VERSION 5.8 ;
BUSBITCHARS "[]" ;
DIVIDERCHAR "/" ;
UNITS
    DATABASE MICRONS 1000 ;
END UNITS

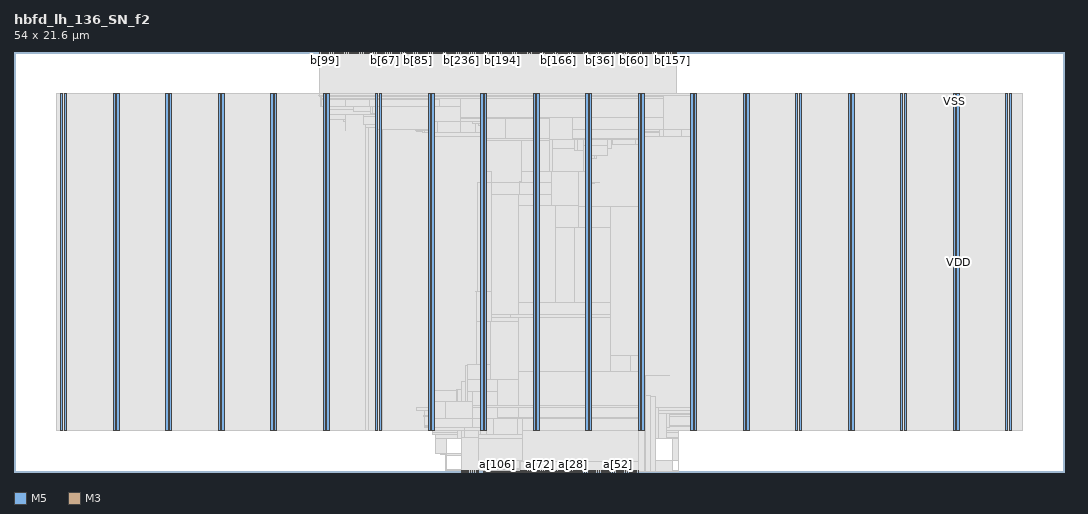
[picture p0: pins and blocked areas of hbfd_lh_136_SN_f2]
MACRO hbfd_lh_136_SN_f2
  FOREIGN hbfd_lh_136_SN_f2 0 0 ;
  CLASS BLOCK ;
  SIZE 54 BY 21.6 ;
  PIN a[0]
    DIRECTION INPUT ;
    USE SIGNAL ;
    PORT
      LAYER M5 ;
        RECT  26.064 0 26.088 0.084 ;
    END
  END a[0]
  PIN a[100]
    DIRECTION INPUT ;
    USE SIGNAL ;
    PORT
      LAYER M3 ;
        RECT  24.444 0 24.462 0.037 ;
    END
  END a[100]
  PIN a[101]
    DIRECTION INPUT ;
    USE SIGNAL ;
    PORT
      LAYER M3 ;
        RECT  24.516 0 24.534 0.037 ;
    END
  END a[101]
  PIN a[102]
    DIRECTION INPUT ;
    USE SIGNAL ;
    PORT
      LAYER M3 ;
        RECT  24.588 0 24.606 0.037 ;
    END
  END a[102]
  PIN a[103]
    DIRECTION INPUT ;
    USE SIGNAL ;
    PORT
      LAYER M3 ;
        RECT  24.66 0 24.678 0.037 ;
    END
  END a[103]
  PIN a[104]
    DIRECTION INPUT ;
    USE SIGNAL ;
    PORT
      LAYER M3 ;
        RECT  24.732 0 24.75 0.037 ;
    END
  END a[104]
  PIN a[105]
    DIRECTION INPUT ;
    USE SIGNAL ;
    PORT
      LAYER M3 ;
        RECT  24.804 0 24.822 0.037 ;
    END
  END a[105]
  PIN a[106]
    DIRECTION INPUT ;
    USE SIGNAL ;
    PORT
      LAYER M3 ;
        RECT  24.876 0 24.894 0.037 ;
    END
  END a[106]
  PIN a[107]
    DIRECTION INPUT ;
    USE SIGNAL ;
    PORT
      LAYER M3 ;
        RECT  24.948 0 24.966 0.037 ;
    END
  END a[107]
  PIN a[108]
    DIRECTION INPUT ;
    USE SIGNAL ;
    PORT
      LAYER M3 ;
        RECT  25.02 0 25.038 0.037 ;
    END
  END a[108]
  PIN a[109]
    DIRECTION INPUT ;
    USE SIGNAL ;
    PORT
      LAYER M3 ;
        RECT  25.092 0 25.11 0.037 ;
    END
  END a[109]
  PIN a[10]
    DIRECTION INPUT ;
    USE SIGNAL ;
    PORT
      LAYER M5 ;
        RECT  27.024 0 27.048 0.084 ;
    END
  END a[10]
  PIN a[110]
    DIRECTION INPUT ;
    USE SIGNAL ;
    PORT
      LAYER M3 ;
        RECT  25.164 0 25.182 0.037 ;
    END
  END a[110]
  PIN a[111]
    DIRECTION INPUT ;
    USE SIGNAL ;
    PORT
      LAYER M3 ;
        RECT  25.236 0 25.254 0.037 ;
    END
  END a[111]
  PIN a[112]
    DIRECTION INPUT ;
    USE SIGNAL ;
    PORT
      LAYER M3 ;
        RECT  25.308 0 25.326 0.037 ;
    END
  END a[112]
  PIN a[113]
    DIRECTION INPUT ;
    USE SIGNAL ;
    PORT
      LAYER M3 ;
        RECT  25.38 0 25.398 0.037 ;
    END
  END a[113]
  PIN a[114]
    DIRECTION INPUT ;
    USE SIGNAL ;
    PORT
      LAYER M3 ;
        RECT  25.452 0 25.47 0.037 ;
    END
  END a[114]
  PIN a[115]
    DIRECTION INPUT ;
    USE SIGNAL ;
    PORT
      LAYER M3 ;
        RECT  25.524 0 25.542 0.037 ;
    END
  END a[115]
  PIN a[116]
    DIRECTION INPUT ;
    USE SIGNAL ;
    PORT
      LAYER M3 ;
        RECT  25.596 0 25.614 0.037 ;
    END
  END a[116]
  PIN a[117]
    DIRECTION INPUT ;
    USE SIGNAL ;
    PORT
      LAYER M3 ;
        RECT  25.668 0 25.686 0.037 ;
    END
  END a[117]
  PIN a[118]
    DIRECTION INPUT ;
    USE SIGNAL ;
    PORT
      LAYER M3 ;
        RECT  25.74 0 25.758 0.037 ;
    END
  END a[118]
  PIN a[119]
    DIRECTION INPUT ;
    USE SIGNAL ;
    PORT
      LAYER M3 ;
        RECT  25.812 0 25.83 0.037 ;
    END
  END a[119]
  PIN a[11]
    DIRECTION INPUT ;
    USE SIGNAL ;
    PORT
      LAYER M5 ;
        RECT  27.12 0 27.144 0.084 ;
    END
  END a[11]
  PIN a[120]
    DIRECTION INPUT ;
    USE SIGNAL ;
    PORT
      LAYER M3 ;
        RECT  25.884 0 25.902 0.037 ;
    END
  END a[120]
  PIN a[121]
    DIRECTION INPUT ;
    USE SIGNAL ;
    PORT
      LAYER M3 ;
        RECT  25.956 0 25.974 0.037 ;
    END
  END a[121]
  PIN a[122]
    DIRECTION INPUT ;
    USE SIGNAL ;
    PORT
      LAYER M3 ;
        RECT  26.028 0 26.046 0.037 ;
    END
  END a[122]
  PIN a[123]
    DIRECTION INPUT ;
    USE SIGNAL ;
    PORT
      LAYER M3 ;
        RECT  26.1 0 26.118 0.037 ;
    END
  END a[123]
  PIN a[124]
    DIRECTION INPUT ;
    USE SIGNAL ;
    PORT
      LAYER M3 ;
        RECT  26.172 0 26.19 0.037 ;
    END
  END a[124]
  PIN a[125]
    DIRECTION INPUT ;
    USE SIGNAL ;
    PORT
      LAYER M3 ;
        RECT  26.244 0 26.262 0.037 ;
    END
  END a[125]
  PIN a[126]
    DIRECTION INPUT ;
    USE SIGNAL ;
    PORT
      LAYER M3 ;
        RECT  26.316 0 26.334 0.037 ;
    END
  END a[126]
  PIN a[127]
    DIRECTION INPUT ;
    USE SIGNAL ;
    PORT
      LAYER M3 ;
        RECT  26.388 0 26.406 0.037 ;
    END
  END a[127]
  PIN a[128]
    DIRECTION INPUT ;
    USE SIGNAL ;
    PORT
      LAYER M5 ;
        RECT  22.992 0 23.016 0.084 ;
    END
  END a[128]
  PIN a[129]
    DIRECTION INPUT ;
    USE SIGNAL ;
    PORT
      LAYER M5 ;
        RECT  23.088 0 23.112 0.084 ;
    END
  END a[129]
  PIN a[12]
    DIRECTION INPUT ;
    USE SIGNAL ;
    PORT
      LAYER M5 ;
        RECT  27.216 0 27.24 0.084 ;
    END
  END a[12]
  PIN a[130]
    DIRECTION INPUT ;
    USE SIGNAL ;
    PORT
      LAYER M5 ;
        RECT  23.184 0 23.208 0.084 ;
    END
  END a[130]
  PIN a[131]
    DIRECTION INPUT ;
    USE SIGNAL ;
    PORT
      LAYER M5 ;
        RECT  23.28 0 23.304 0.084 ;
    END
  END a[131]
  PIN a[132]
    DIRECTION INPUT ;
    USE SIGNAL ;
    PORT
      LAYER M5 ;
        RECT  23.376 0 23.4 0.084 ;
    END
  END a[132]
  PIN a[133]
    DIRECTION INPUT ;
    USE SIGNAL ;
    PORT
      LAYER M5 ;
        RECT  23.472 0 23.496 0.084 ;
    END
  END a[133]
  PIN a[134]
    DIRECTION INPUT ;
    USE SIGNAL ;
    PORT
      LAYER M5 ;
        RECT  23.568 0 23.592 0.084 ;
    END
  END a[134]
  PIN a[135]
    DIRECTION INPUT ;
    USE SIGNAL ;
    PORT
      LAYER M5 ;
        RECT  23.664 0 23.688 0.084 ;
    END
  END a[135]
  PIN a[13]
    DIRECTION INPUT ;
    USE SIGNAL ;
    PORT
      LAYER M5 ;
        RECT  27.312 0 27.336 0.084 ;
    END
  END a[13]
  PIN a[14]
    DIRECTION INPUT ;
    USE SIGNAL ;
    PORT
      LAYER M5 ;
        RECT  27.408 0 27.432 0.084 ;
    END
  END a[14]
  PIN a[15]
    DIRECTION INPUT ;
    USE SIGNAL ;
    PORT
      LAYER M5 ;
        RECT  27.504 0 27.528 0.084 ;
    END
  END a[15]
  PIN a[16]
    DIRECTION INPUT ;
    USE SIGNAL ;
    PORT
      LAYER M5 ;
        RECT  27.6 0 27.624 0.084 ;
    END
  END a[16]
  PIN a[17]
    DIRECTION INPUT ;
    USE SIGNAL ;
    PORT
      LAYER M5 ;
        RECT  27.696 0 27.72 0.084 ;
    END
  END a[17]
  PIN a[18]
    DIRECTION INPUT ;
    USE SIGNAL ;
    PORT
      LAYER M5 ;
        RECT  27.792 0 27.816 0.084 ;
    END
  END a[18]
  PIN a[19]
    DIRECTION INPUT ;
    USE SIGNAL ;
    PORT
      LAYER M5 ;
        RECT  27.888 0 27.912 0.084 ;
    END
  END a[19]
  PIN a[1]
    DIRECTION INPUT ;
    USE SIGNAL ;
    PORT
      LAYER M5 ;
        RECT  26.16 0 26.184 0.084 ;
    END
  END a[1]
  PIN a[20]
    DIRECTION INPUT ;
    USE SIGNAL ;
    PORT
      LAYER M5 ;
        RECT  27.984 0 28.008 0.084 ;
    END
  END a[20]
  PIN a[21]
    DIRECTION INPUT ;
    USE SIGNAL ;
    PORT
      LAYER M5 ;
        RECT  28.08 0 28.104 0.084 ;
    END
  END a[21]
  PIN a[22]
    DIRECTION INPUT ;
    USE SIGNAL ;
    PORT
      LAYER M5 ;
        RECT  28.176 0 28.2 0.084 ;
    END
  END a[22]
  PIN a[23]
    DIRECTION INPUT ;
    USE SIGNAL ;
    PORT
      LAYER M5 ;
        RECT  28.272 0 28.296 0.084 ;
    END
  END a[23]
  PIN a[24]
    DIRECTION INPUT ;
    USE SIGNAL ;
    PORT
      LAYER M5 ;
        RECT  28.368 0 28.392 0.084 ;
    END
  END a[24]
  PIN a[25]
    DIRECTION INPUT ;
    USE SIGNAL ;
    PORT
      LAYER M5 ;
        RECT  28.464 0 28.488 0.084 ;
    END
  END a[25]
  PIN a[26]
    DIRECTION INPUT ;
    USE SIGNAL ;
    PORT
      LAYER M5 ;
        RECT  28.56 0 28.584 0.084 ;
    END
  END a[26]
  PIN a[27]
    DIRECTION INPUT ;
    USE SIGNAL ;
    PORT
      LAYER M5 ;
        RECT  28.656 0 28.68 0.084 ;
    END
  END a[27]
  PIN a[28]
    DIRECTION INPUT ;
    USE SIGNAL ;
    PORT
      LAYER M5 ;
        RECT  28.752 0 28.776 0.084 ;
    END
  END a[28]
  PIN a[29]
    DIRECTION INPUT ;
    USE SIGNAL ;
    PORT
      LAYER M5 ;
        RECT  28.848 0 28.872 0.084 ;
    END
  END a[29]
  PIN a[2]
    DIRECTION INPUT ;
    USE SIGNAL ;
    PORT
      LAYER M5 ;
        RECT  26.256 0 26.28 0.084 ;
    END
  END a[2]
  PIN a[30]
    DIRECTION INPUT ;
    USE SIGNAL ;
    PORT
      LAYER M5 ;
        RECT  28.944 0 28.968 0.084 ;
    END
  END a[30]
  PIN a[31]
    DIRECTION INPUT ;
    USE SIGNAL ;
    PORT
      LAYER M5 ;
        RECT  29.04 0 29.064 0.084 ;
    END
  END a[31]
  PIN a[32]
    DIRECTION INPUT ;
    USE SIGNAL ;
    PORT
      LAYER M5 ;
        RECT  29.136 0 29.16 0.084 ;
    END
  END a[32]
  PIN a[33]
    DIRECTION INPUT ;
    USE SIGNAL ;
    PORT
      LAYER M5 ;
        RECT  29.232 0 29.256 0.084 ;
    END
  END a[33]
  PIN a[34]
    DIRECTION INPUT ;
    USE SIGNAL ;
    PORT
      LAYER M5 ;
        RECT  29.328 0 29.352 0.084 ;
    END
  END a[34]
  PIN a[35]
    DIRECTION INPUT ;
    USE SIGNAL ;
    PORT
      LAYER M5 ;
        RECT  29.424 0 29.448 0.084 ;
    END
  END a[35]
  PIN a[36]
    DIRECTION INPUT ;
    USE SIGNAL ;
    PORT
      LAYER M5 ;
        RECT  29.52 0 29.544 0.084 ;
    END
  END a[36]
  PIN a[37]
    DIRECTION INPUT ;
    USE SIGNAL ;
    PORT
      LAYER M5 ;
        RECT  29.616 0 29.64 0.084 ;
    END
  END a[37]
  PIN a[38]
    DIRECTION INPUT ;
    USE SIGNAL ;
    PORT
      LAYER M5 ;
        RECT  29.712 0 29.736 0.084 ;
    END
  END a[38]
  PIN a[39]
    DIRECTION INPUT ;
    USE SIGNAL ;
    PORT
      LAYER M5 ;
        RECT  29.808 0 29.832 0.084 ;
    END
  END a[39]
  PIN a[3]
    DIRECTION INPUT ;
    USE SIGNAL ;
    PORT
      LAYER M5 ;
        RECT  26.352 0 26.376 0.084 ;
    END
  END a[3]
  PIN a[40]
    DIRECTION INPUT ;
    USE SIGNAL ;
    PORT
      LAYER M5 ;
        RECT  29.904 0 29.928 0.084 ;
    END
  END a[40]
  PIN a[41]
    DIRECTION INPUT ;
    USE SIGNAL ;
    PORT
      LAYER M5 ;
        RECT  30 0 30.024 0.084 ;
    END
  END a[41]
  PIN a[42]
    DIRECTION INPUT ;
    USE SIGNAL ;
    PORT
      LAYER M5 ;
        RECT  30.096 0 30.12 0.084 ;
    END
  END a[42]
  PIN a[43]
    DIRECTION INPUT ;
    USE SIGNAL ;
    PORT
      LAYER M5 ;
        RECT  30.192 0 30.216 0.084 ;
    END
  END a[43]
  PIN a[44]
    DIRECTION INPUT ;
    USE SIGNAL ;
    PORT
      LAYER M5 ;
        RECT  30.288 0 30.312 0.084 ;
    END
  END a[44]
  PIN a[45]
    DIRECTION INPUT ;
    USE SIGNAL ;
    PORT
      LAYER M5 ;
        RECT  30.384 0 30.408 0.084 ;
    END
  END a[45]
  PIN a[46]
    DIRECTION INPUT ;
    USE SIGNAL ;
    PORT
      LAYER M5 ;
        RECT  30.48 0 30.504 0.084 ;
    END
  END a[46]
  PIN a[47]
    DIRECTION INPUT ;
    USE SIGNAL ;
    PORT
      LAYER M5 ;
        RECT  30.576 0 30.6 0.084 ;
    END
  END a[47]
  PIN a[48]
    DIRECTION INPUT ;
    USE SIGNAL ;
    PORT
      LAYER M5 ;
        RECT  30.672 0 30.696 0.084 ;
    END
  END a[48]
  PIN a[49]
    DIRECTION INPUT ;
    USE SIGNAL ;
    PORT
      LAYER M5 ;
        RECT  30.768 0 30.792 0.084 ;
    END
  END a[49]
  PIN a[4]
    DIRECTION INPUT ;
    USE SIGNAL ;
    PORT
      LAYER M5 ;
        RECT  26.448 0 26.472 0.084 ;
    END
  END a[4]
  PIN a[50]
    DIRECTION INPUT ;
    USE SIGNAL ;
    PORT
      LAYER M5 ;
        RECT  30.864 0 30.888 0.084 ;
    END
  END a[50]
  PIN a[51]
    DIRECTION INPUT ;
    USE SIGNAL ;
    PORT
      LAYER M5 ;
        RECT  30.96 0 30.984 0.084 ;
    END
  END a[51]
  PIN a[52]
    DIRECTION INPUT ;
    USE SIGNAL ;
    PORT
      LAYER M5 ;
        RECT  31.056 0 31.08 0.084 ;
    END
  END a[52]
  PIN a[53]
    DIRECTION INPUT ;
    USE SIGNAL ;
    PORT
      LAYER M5 ;
        RECT  31.152 0 31.176 0.084 ;
    END
  END a[53]
  PIN a[54]
    DIRECTION INPUT ;
    USE SIGNAL ;
    PORT
      LAYER M5 ;
        RECT  31.248 0 31.272 0.084 ;
    END
  END a[54]
  PIN a[55]
    DIRECTION INPUT ;
    USE SIGNAL ;
    PORT
      LAYER M5 ;
        RECT  31.344 0 31.368 0.084 ;
    END
  END a[55]
  PIN a[56]
    DIRECTION INPUT ;
    USE SIGNAL ;
    PORT
      LAYER M5 ;
        RECT  31.44 0 31.464 0.084 ;
    END
  END a[56]
  PIN a[57]
    DIRECTION INPUT ;
    USE SIGNAL ;
    PORT
      LAYER M5 ;
        RECT  31.536 0 31.56 0.084 ;
    END
  END a[57]
  PIN a[58]
    DIRECTION INPUT ;
    USE SIGNAL ;
    PORT
      LAYER M5 ;
        RECT  31.632 0 31.656 0.084 ;
    END
  END a[58]
  PIN a[59]
    DIRECTION INPUT ;
    USE SIGNAL ;
    PORT
      LAYER M5 ;
        RECT  31.728 0 31.752 0.084 ;
    END
  END a[59]
  PIN a[5]
    DIRECTION INPUT ;
    USE SIGNAL ;
    PORT
      LAYER M5 ;
        RECT  26.544 0 26.568 0.084 ;
    END
  END a[5]
  PIN a[60]
    DIRECTION INPUT ;
    USE SIGNAL ;
    PORT
      LAYER M5 ;
        RECT  31.824 0 31.848 0.084 ;
    END
  END a[60]
  PIN a[61]
    DIRECTION INPUT ;
    USE SIGNAL ;
    PORT
      LAYER M5 ;
        RECT  31.92 0 31.944 0.084 ;
    END
  END a[61]
  PIN a[62]
    DIRECTION INPUT ;
    USE SIGNAL ;
    PORT
      LAYER M5 ;
        RECT  32.016 0 32.04 0.084 ;
    END
  END a[62]
  PIN a[63]
    DIRECTION INPUT ;
    USE SIGNAL ;
    PORT
      LAYER M5 ;
        RECT  32.112 0 32.136 0.084 ;
    END
  END a[63]
  PIN a[64]
    DIRECTION INPUT ;
    USE SIGNAL ;
    PORT
      LAYER M3 ;
        RECT  26.46 0 26.478 0.037 ;
    END
  END a[64]
  PIN a[65]
    DIRECTION INPUT ;
    USE SIGNAL ;
    PORT
      LAYER M3 ;
        RECT  26.532 0 26.55 0.037 ;
    END
  END a[65]
  PIN a[66]
    DIRECTION INPUT ;
    USE SIGNAL ;
    PORT
      LAYER M3 ;
        RECT  26.604 0 26.622 0.037 ;
    END
  END a[66]
  PIN a[67]
    DIRECTION INPUT ;
    USE SIGNAL ;
    PORT
      LAYER M3 ;
        RECT  26.676 0 26.694 0.037 ;
    END
  END a[67]
  PIN a[68]
    DIRECTION INPUT ;
    USE SIGNAL ;
    PORT
      LAYER M3 ;
        RECT  26.748 0 26.766 0.037 ;
    END
  END a[68]
  PIN a[69]
    DIRECTION INPUT ;
    USE SIGNAL ;
    PORT
      LAYER M3 ;
        RECT  26.82 0 26.838 0.037 ;
    END
  END a[69]
  PIN a[6]
    DIRECTION INPUT ;
    USE SIGNAL ;
    PORT
      LAYER M5 ;
        RECT  26.64 0 26.664 0.084 ;
    END
  END a[6]
  PIN a[70]
    DIRECTION INPUT ;
    USE SIGNAL ;
    PORT
      LAYER M3 ;
        RECT  26.892 0 26.91 0.037 ;
    END
  END a[70]
  PIN a[71]
    DIRECTION INPUT ;
    USE SIGNAL ;
    PORT
      LAYER M3 ;
        RECT  26.964 0 26.982 0.037 ;
    END
  END a[71]
  PIN a[72]
    DIRECTION INPUT ;
    USE SIGNAL ;
    PORT
      LAYER M3 ;
        RECT  27.036 0 27.054 0.037 ;
    END
  END a[72]
  PIN a[73]
    DIRECTION INPUT ;
    USE SIGNAL ;
    PORT
      LAYER M3 ;
        RECT  27.108 0 27.126 0.037 ;
    END
  END a[73]
  PIN a[74]
    DIRECTION INPUT ;
    USE SIGNAL ;
    PORT
      LAYER M3 ;
        RECT  27.18 0 27.198 0.037 ;
    END
  END a[74]
  PIN a[75]
    DIRECTION INPUT ;
    USE SIGNAL ;
    PORT
      LAYER M3 ;
        RECT  27.252 0 27.27 0.037 ;
    END
  END a[75]
  PIN a[76]
    DIRECTION INPUT ;
    USE SIGNAL ;
    PORT
      LAYER M3 ;
        RECT  27.324 0 27.342 0.037 ;
    END
  END a[76]
  PIN a[77]
    DIRECTION INPUT ;
    USE SIGNAL ;
    PORT
      LAYER M3 ;
        RECT  27.396 0 27.414 0.037 ;
    END
  END a[77]
  PIN a[78]
    DIRECTION INPUT ;
    USE SIGNAL ;
    PORT
      LAYER M3 ;
        RECT  27.468 0 27.486 0.037 ;
    END
  END a[78]
  PIN a[79]
    DIRECTION INPUT ;
    USE SIGNAL ;
    PORT
      LAYER M3 ;
        RECT  27.54 0 27.558 0.037 ;
    END
  END a[79]
  PIN a[7]
    DIRECTION INPUT ;
    USE SIGNAL ;
    PORT
      LAYER M5 ;
        RECT  26.736 0 26.76 0.084 ;
    END
  END a[7]
  PIN a[80]
    DIRECTION INPUT ;
    USE SIGNAL ;
    PORT
      LAYER M3 ;
        RECT  27.612 0 27.63 0.037 ;
    END
  END a[80]
  PIN a[81]
    DIRECTION INPUT ;
    USE SIGNAL ;
    PORT
      LAYER M3 ;
        RECT  27.684 0 27.702 0.037 ;
    END
  END a[81]
  PIN a[82]
    DIRECTION INPUT ;
    USE SIGNAL ;
    PORT
      LAYER M3 ;
        RECT  27.756 0 27.774 0.037 ;
    END
  END a[82]
  PIN a[83]
    DIRECTION INPUT ;
    USE SIGNAL ;
    PORT
      LAYER M3 ;
        RECT  27.828 0 27.846 0.037 ;
    END
  END a[83]
  PIN a[84]
    DIRECTION INPUT ;
    USE SIGNAL ;
    PORT
      LAYER M3 ;
        RECT  27.9 0 27.918 0.037 ;
    END
  END a[84]
  PIN a[85]
    DIRECTION INPUT ;
    USE SIGNAL ;
    PORT
      LAYER M3 ;
        RECT  27.972 0 27.99 0.037 ;
    END
  END a[85]
  PIN a[86]
    DIRECTION INPUT ;
    USE SIGNAL ;
    PORT
      LAYER M3 ;
        RECT  28.044 0 28.062 0.037 ;
    END
  END a[86]
  PIN a[87]
    DIRECTION INPUT ;
    USE SIGNAL ;
    PORT
      LAYER M3 ;
        RECT  28.116 0 28.134 0.037 ;
    END
  END a[87]
  PIN a[88]
    DIRECTION INPUT ;
    USE SIGNAL ;
    PORT
      LAYER M3 ;
        RECT  28.188 0 28.206 0.037 ;
    END
  END a[88]
  PIN a[89]
    DIRECTION INPUT ;
    USE SIGNAL ;
    PORT
      LAYER M3 ;
        RECT  28.26 0 28.278 0.037 ;
    END
  END a[89]
  PIN a[8]
    DIRECTION INPUT ;
    USE SIGNAL ;
    PORT
      LAYER M5 ;
        RECT  26.832 0 26.856 0.084 ;
    END
  END a[8]
  PIN a[90]
    DIRECTION INPUT ;
    USE SIGNAL ;
    PORT
      LAYER M3 ;
        RECT  28.332 0 28.35 0.037 ;
    END
  END a[90]
  PIN a[91]
    DIRECTION INPUT ;
    USE SIGNAL ;
    PORT
      LAYER M3 ;
        RECT  28.404 0 28.422 0.037 ;
    END
  END a[91]
  PIN a[92]
    DIRECTION INPUT ;
    USE SIGNAL ;
    PORT
      LAYER M3 ;
        RECT  28.476 0 28.494 0.037 ;
    END
  END a[92]
  PIN a[93]
    DIRECTION INPUT ;
    USE SIGNAL ;
    PORT
      LAYER M3 ;
        RECT  28.548 0 28.566 0.037 ;
    END
  END a[93]
  PIN a[94]
    DIRECTION INPUT ;
    USE SIGNAL ;
    PORT
      LAYER M3 ;
        RECT  28.62 0 28.638 0.037 ;
    END
  END a[94]
  PIN a[95]
    DIRECTION INPUT ;
    USE SIGNAL ;
    PORT
      LAYER M3 ;
        RECT  28.692 0 28.71 0.037 ;
    END
  END a[95]
  PIN a[96]
    DIRECTION INPUT ;
    USE SIGNAL ;
    PORT
      LAYER M3 ;
        RECT  24.156 0 24.174 0.037 ;
    END
  END a[96]
  PIN a[97]
    DIRECTION INPUT ;
    USE SIGNAL ;
    PORT
      LAYER M3 ;
        RECT  24.228 0 24.246 0.037 ;
    END
  END a[97]
  PIN a[98]
    DIRECTION INPUT ;
    USE SIGNAL ;
    PORT
      LAYER M3 ;
        RECT  24.3 0 24.318 0.037 ;
    END
  END a[98]
  PIN a[99]
    DIRECTION INPUT ;
    USE SIGNAL ;
    PORT
      LAYER M3 ;
        RECT  24.372 0 24.39 0.037 ;
    END
  END a[99]
  PIN a[9]
    DIRECTION INPUT ;
    USE SIGNAL ;
    PORT
      LAYER M5 ;
        RECT  26.928 0 26.952 0.084 ;
    END
  END a[9]
  PIN b[0]
    DIRECTION OUTPUT ;
    USE SIGNAL ;
    PORT
      LAYER M5 ;
        RECT  27.984 21.516 28.008 21.6 ;
    END
  END b[0]
  PIN b[100]
    DIRECTION OUTPUT ;
    USE SIGNAL ;
    PORT
      LAYER M5 ;
        RECT  16.08 21.516 16.104 21.6 ;
    END
  END b[100]
  PIN b[101]
    DIRECTION OUTPUT ;
    USE SIGNAL ;
    PORT
      LAYER M5 ;
        RECT  16.176 21.516 16.2 21.6 ;
    END
  END b[101]
  PIN b[102]
    DIRECTION OUTPUT ;
    USE SIGNAL ;
    PORT
      LAYER M5 ;
        RECT  16.272 21.516 16.296 21.6 ;
    END
  END b[102]
  PIN b[103]
    DIRECTION OUTPUT ;
    USE SIGNAL ;
    PORT
      LAYER M5 ;
        RECT  16.368 21.516 16.392 21.6 ;
    END
  END b[103]
  PIN b[104]
    DIRECTION OUTPUT ;
    USE SIGNAL ;
    PORT
      LAYER M5 ;
        RECT  16.464 21.516 16.488 21.6 ;
    END
  END b[104]
  PIN b[105]
    DIRECTION OUTPUT ;
    USE SIGNAL ;
    PORT
      LAYER M5 ;
        RECT  16.56 21.516 16.584 21.6 ;
    END
  END b[105]
  PIN b[106]
    DIRECTION OUTPUT ;
    USE SIGNAL ;
    PORT
      LAYER M5 ;
        RECT  16.656 21.516 16.68 21.6 ;
    END
  END b[106]
  PIN b[107]
    DIRECTION OUTPUT ;
    USE SIGNAL ;
    PORT
      LAYER M5 ;
        RECT  16.752 21.516 16.776 21.6 ;
    END
  END b[107]
  PIN b[108]
    DIRECTION OUTPUT ;
    USE SIGNAL ;
    PORT
      LAYER M5 ;
        RECT  16.848 21.516 16.872 21.6 ;
    END
  END b[108]
  PIN b[109]
    DIRECTION OUTPUT ;
    USE SIGNAL ;
    PORT
      LAYER M5 ;
        RECT  16.944 21.516 16.968 21.6 ;
    END
  END b[109]
  PIN b[10]
    DIRECTION OUTPUT ;
    USE SIGNAL ;
    PORT
      LAYER M5 ;
        RECT  28.944 21.516 28.968 21.6 ;
    END
  END b[10]
  PIN b[110]
    DIRECTION OUTPUT ;
    USE SIGNAL ;
    PORT
      LAYER M5 ;
        RECT  17.04 21.516 17.064 21.6 ;
    END
  END b[110]
  PIN b[111]
    DIRECTION OUTPUT ;
    USE SIGNAL ;
    PORT
      LAYER M5 ;
        RECT  17.136 21.516 17.16 21.6 ;
    END
  END b[111]
  PIN b[112]
    DIRECTION OUTPUT ;
    USE SIGNAL ;
    PORT
      LAYER M5 ;
        RECT  17.232 21.516 17.256 21.6 ;
    END
  END b[112]
  PIN b[113]
    DIRECTION OUTPUT ;
    USE SIGNAL ;
    PORT
      LAYER M5 ;
        RECT  17.328 21.516 17.352 21.6 ;
    END
  END b[113]
  PIN b[114]
    DIRECTION OUTPUT ;
    USE SIGNAL ;
    PORT
      LAYER M5 ;
        RECT  17.424 21.516 17.448 21.6 ;
    END
  END b[114]
  PIN b[115]
    DIRECTION OUTPUT ;
    USE SIGNAL ;
    PORT
      LAYER M5 ;
        RECT  17.52 21.516 17.544 21.6 ;
    END
  END b[115]
  PIN b[116]
    DIRECTION OUTPUT ;
    USE SIGNAL ;
    PORT
      LAYER M5 ;
        RECT  17.616 21.516 17.64 21.6 ;
    END
  END b[116]
  PIN b[117]
    DIRECTION OUTPUT ;
    USE SIGNAL ;
    PORT
      LAYER M5 ;
        RECT  17.712 21.516 17.736 21.6 ;
    END
  END b[117]
  PIN b[118]
    DIRECTION OUTPUT ;
    USE SIGNAL ;
    PORT
      LAYER M5 ;
        RECT  17.808 21.516 17.832 21.6 ;
    END
  END b[118]
  PIN b[119]
    DIRECTION OUTPUT ;
    USE SIGNAL ;
    PORT
      LAYER M5 ;
        RECT  17.904 21.516 17.928 21.6 ;
    END
  END b[119]
  PIN b[11]
    DIRECTION OUTPUT ;
    USE SIGNAL ;
    PORT
      LAYER M5 ;
        RECT  29.04 21.516 29.064 21.6 ;
    END
  END b[11]
  PIN b[120]
    DIRECTION OUTPUT ;
    USE SIGNAL ;
    PORT
      LAYER M5 ;
        RECT  18 21.516 18.024 21.6 ;
    END
  END b[120]
  PIN b[121]
    DIRECTION OUTPUT ;
    USE SIGNAL ;
    PORT
      LAYER M5 ;
        RECT  18.096 21.516 18.12 21.6 ;
    END
  END b[121]
  PIN b[122]
    DIRECTION OUTPUT ;
    USE SIGNAL ;
    PORT
      LAYER M5 ;
        RECT  18.192 21.516 18.216 21.6 ;
    END
  END b[122]
  PIN b[123]
    DIRECTION OUTPUT ;
    USE SIGNAL ;
    PORT
      LAYER M5 ;
        RECT  18.288 21.516 18.312 21.6 ;
    END
  END b[123]
  PIN b[124]
    DIRECTION OUTPUT ;
    USE SIGNAL ;
    PORT
      LAYER M5 ;
        RECT  18.384 21.516 18.408 21.6 ;
    END
  END b[124]
  PIN b[125]
    DIRECTION OUTPUT ;
    USE SIGNAL ;
    PORT
      LAYER M5 ;
        RECT  18.48 21.516 18.504 21.6 ;
    END
  END b[125]
  PIN b[126]
    DIRECTION OUTPUT ;
    USE SIGNAL ;
    PORT
      LAYER M5 ;
        RECT  18.576 21.516 18.6 21.6 ;
    END
  END b[126]
  PIN b[127]
    DIRECTION OUTPUT ;
    USE SIGNAL ;
    PORT
      LAYER M5 ;
        RECT  18.672 21.516 18.696 21.6 ;
    END
  END b[127]
  PIN b[128]
    DIRECTION OUTPUT ;
    USE SIGNAL ;
    PORT
      LAYER M5 ;
        RECT  31.056 21.516 31.08 21.6 ;
    END
  END b[128]
  PIN b[129]
    DIRECTION OUTPUT ;
    USE SIGNAL ;
    PORT
      LAYER M5 ;
        RECT  31.152 21.516 31.176 21.6 ;
    END
  END b[129]
  PIN b[12]
    DIRECTION OUTPUT ;
    USE SIGNAL ;
    PORT
      LAYER M5 ;
        RECT  29.136 21.516 29.16 21.6 ;
    END
  END b[12]
  PIN b[130]
    DIRECTION OUTPUT ;
    USE SIGNAL ;
    PORT
      LAYER M5 ;
        RECT  31.248 21.516 31.272 21.6 ;
    END
  END b[130]
  PIN b[131]
    DIRECTION OUTPUT ;
    USE SIGNAL ;
    PORT
      LAYER M5 ;
        RECT  31.344 21.516 31.368 21.6 ;
    END
  END b[131]
  PIN b[132]
    DIRECTION OUTPUT ;
    USE SIGNAL ;
    PORT
      LAYER M5 ;
        RECT  31.44 21.516 31.464 21.6 ;
    END
  END b[132]
  PIN b[133]
    DIRECTION OUTPUT ;
    USE SIGNAL ;
    PORT
      LAYER M5 ;
        RECT  31.536 21.516 31.56 21.6 ;
    END
  END b[133]
  PIN b[134]
    DIRECTION OUTPUT ;
    USE SIGNAL ;
    PORT
      LAYER M5 ;
        RECT  31.632 21.516 31.656 21.6 ;
    END
  END b[134]
  PIN b[135]
    DIRECTION OUTPUT ;
    USE SIGNAL ;
    PORT
      LAYER M5 ;
        RECT  31.728 21.516 31.752 21.6 ;
    END
  END b[135]
  PIN b[136]
    DIRECTION OUTPUT ;
    USE SIGNAL ;
    PORT
      LAYER M5 ;
        RECT  31.824 21.516 31.848 21.6 ;
    END
  END b[136]
  PIN b[137]
    DIRECTION OUTPUT ;
    USE SIGNAL ;
    PORT
      LAYER M5 ;
        RECT  31.92 21.516 31.944 21.6 ;
    END
  END b[137]
  PIN b[138]
    DIRECTION OUTPUT ;
    USE SIGNAL ;
    PORT
      LAYER M5 ;
        RECT  32.016 21.516 32.04 21.6 ;
    END
  END b[138]
  PIN b[139]
    DIRECTION OUTPUT ;
    USE SIGNAL ;
    PORT
      LAYER M5 ;
        RECT  32.112 21.516 32.136 21.6 ;
    END
  END b[139]
  PIN b[13]
    DIRECTION OUTPUT ;
    USE SIGNAL ;
    PORT
      LAYER M5 ;
        RECT  29.232 21.516 29.256 21.6 ;
    END
  END b[13]
  PIN b[140]
    DIRECTION OUTPUT ;
    USE SIGNAL ;
    PORT
      LAYER M5 ;
        RECT  32.208 21.516 32.232 21.6 ;
    END
  END b[140]
  PIN b[141]
    DIRECTION OUTPUT ;
    USE SIGNAL ;
    PORT
      LAYER M5 ;
        RECT  32.304 21.516 32.328 21.6 ;
    END
  END b[141]
  PIN b[142]
    DIRECTION OUTPUT ;
    USE SIGNAL ;
    PORT
      LAYER M5 ;
        RECT  32.4 21.516 32.424 21.6 ;
    END
  END b[142]
  PIN b[143]
    DIRECTION OUTPUT ;
    USE SIGNAL ;
    PORT
      LAYER M5 ;
        RECT  32.496 21.516 32.52 21.6 ;
    END
  END b[143]
  PIN b[144]
    DIRECTION OUTPUT ;
    USE SIGNAL ;
    PORT
      LAYER M5 ;
        RECT  32.592 21.516 32.616 21.6 ;
    END
  END b[144]
  PIN b[145]
    DIRECTION OUTPUT ;
    USE SIGNAL ;
    PORT
      LAYER M5 ;
        RECT  32.688 21.516 32.712 21.6 ;
    END
  END b[145]
  PIN b[146]
    DIRECTION OUTPUT ;
    USE SIGNAL ;
    PORT
      LAYER M5 ;
        RECT  32.784 21.516 32.808 21.6 ;
    END
  END b[146]
  PIN b[147]
    DIRECTION OUTPUT ;
    USE SIGNAL ;
    PORT
      LAYER M5 ;
        RECT  32.88 21.516 32.904 21.6 ;
    END
  END b[147]
  PIN b[148]
    DIRECTION OUTPUT ;
    USE SIGNAL ;
    PORT
      LAYER M5 ;
        RECT  32.976 21.516 33 21.6 ;
    END
  END b[148]
  PIN b[149]
    DIRECTION OUTPUT ;
    USE SIGNAL ;
    PORT
      LAYER M5 ;
        RECT  33.072 21.516 33.096 21.6 ;
    END
  END b[149]
  PIN b[14]
    DIRECTION OUTPUT ;
    USE SIGNAL ;
    PORT
      LAYER M5 ;
        RECT  29.328 21.516 29.352 21.6 ;
    END
  END b[14]
  PIN b[150]
    DIRECTION OUTPUT ;
    USE SIGNAL ;
    PORT
      LAYER M5 ;
        RECT  33.168 21.516 33.192 21.6 ;
    END
  END b[150]
  PIN b[151]
    DIRECTION OUTPUT ;
    USE SIGNAL ;
    PORT
      LAYER M5 ;
        RECT  33.264 21.516 33.288 21.6 ;
    END
  END b[151]
  PIN b[152]
    DIRECTION OUTPUT ;
    USE SIGNAL ;
    PORT
      LAYER M5 ;
        RECT  33.36 21.516 33.384 21.6 ;
    END
  END b[152]
  PIN b[153]
    DIRECTION OUTPUT ;
    USE SIGNAL ;
    PORT
      LAYER M5 ;
        RECT  33.456 21.516 33.48 21.6 ;
    END
  END b[153]
  PIN b[154]
    DIRECTION OUTPUT ;
    USE SIGNAL ;
    PORT
      LAYER M5 ;
        RECT  33.552 21.516 33.576 21.6 ;
    END
  END b[154]
  PIN b[155]
    DIRECTION OUTPUT ;
    USE SIGNAL ;
    PORT
      LAYER M5 ;
        RECT  33.648 21.516 33.672 21.6 ;
    END
  END b[155]
  PIN b[156]
    DIRECTION OUTPUT ;
    USE SIGNAL ;
    PORT
      LAYER M5 ;
        RECT  33.744 21.516 33.768 21.6 ;
    END
  END b[156]
  PIN b[157]
    DIRECTION OUTPUT ;
    USE SIGNAL ;
    PORT
      LAYER M5 ;
        RECT  33.84 21.516 33.864 21.6 ;
    END
  END b[157]
  PIN b[158]
    DIRECTION OUTPUT ;
    USE SIGNAL ;
    PORT
      LAYER M5 ;
        RECT  33.936 21.516 33.96 21.6 ;
    END
  END b[158]
  PIN b[159]
    DIRECTION OUTPUT ;
    USE SIGNAL ;
    PORT
      LAYER M5 ;
        RECT  34.032 21.516 34.056 21.6 ;
    END
  END b[159]
  PIN b[15]
    DIRECTION OUTPUT ;
    USE SIGNAL ;
    PORT
      LAYER M5 ;
        RECT  29.424 21.516 29.448 21.6 ;
    END
  END b[15]
  PIN b[160]
    DIRECTION OUTPUT ;
    USE SIGNAL ;
    PORT
      LAYER M3 ;
        RECT  27.54 21.563 27.558 21.6 ;
    END
  END b[160]
  PIN b[161]
    DIRECTION OUTPUT ;
    USE SIGNAL ;
    PORT
      LAYER M3 ;
        RECT  27.612 21.563 27.63 21.6 ;
    END
  END b[161]
  PIN b[162]
    DIRECTION OUTPUT ;
    USE SIGNAL ;
    PORT
      LAYER M3 ;
        RECT  27.684 21.563 27.702 21.6 ;
    END
  END b[162]
  PIN b[163]
    DIRECTION OUTPUT ;
    USE SIGNAL ;
    PORT
      LAYER M3 ;
        RECT  27.756 21.563 27.774 21.6 ;
    END
  END b[163]
  PIN b[164]
    DIRECTION OUTPUT ;
    USE SIGNAL ;
    PORT
      LAYER M3 ;
        RECT  27.828 21.563 27.846 21.6 ;
    END
  END b[164]
  PIN b[165]
    DIRECTION OUTPUT ;
    USE SIGNAL ;
    PORT
      LAYER M3 ;
        RECT  27.9 21.563 27.918 21.6 ;
    END
  END b[165]
  PIN b[166]
    DIRECTION OUTPUT ;
    USE SIGNAL ;
    PORT
      LAYER M3 ;
        RECT  27.972 21.563 27.99 21.6 ;
    END
  END b[166]
  PIN b[167]
    DIRECTION OUTPUT ;
    USE SIGNAL ;
    PORT
      LAYER M3 ;
        RECT  28.044 21.563 28.062 21.6 ;
    END
  END b[167]
  PIN b[168]
    DIRECTION OUTPUT ;
    USE SIGNAL ;
    PORT
      LAYER M3 ;
        RECT  28.116 21.563 28.134 21.6 ;
    END
  END b[168]
  PIN b[169]
    DIRECTION OUTPUT ;
    USE SIGNAL ;
    PORT
      LAYER M3 ;
        RECT  28.188 21.563 28.206 21.6 ;
    END
  END b[169]
  PIN b[16]
    DIRECTION OUTPUT ;
    USE SIGNAL ;
    PORT
      LAYER M5 ;
        RECT  29.52 21.516 29.544 21.6 ;
    END
  END b[16]
  PIN b[170]
    DIRECTION OUTPUT ;
    USE SIGNAL ;
    PORT
      LAYER M3 ;
        RECT  28.26 21.563 28.278 21.6 ;
    END
  END b[170]
  PIN b[171]
    DIRECTION OUTPUT ;
    USE SIGNAL ;
    PORT
      LAYER M3 ;
        RECT  28.332 21.563 28.35 21.6 ;
    END
  END b[171]
  PIN b[172]
    DIRECTION OUTPUT ;
    USE SIGNAL ;
    PORT
      LAYER M3 ;
        RECT  28.404 21.563 28.422 21.6 ;
    END
  END b[172]
  PIN b[173]
    DIRECTION OUTPUT ;
    USE SIGNAL ;
    PORT
      LAYER M3 ;
        RECT  28.476 21.563 28.494 21.6 ;
    END
  END b[173]
  PIN b[174]
    DIRECTION OUTPUT ;
    USE SIGNAL ;
    PORT
      LAYER M3 ;
        RECT  28.548 21.563 28.566 21.6 ;
    END
  END b[174]
  PIN b[175]
    DIRECTION OUTPUT ;
    USE SIGNAL ;
    PORT
      LAYER M3 ;
        RECT  28.62 21.563 28.638 21.6 ;
    END
  END b[175]
  PIN b[176]
    DIRECTION OUTPUT ;
    USE SIGNAL ;
    PORT
      LAYER M3 ;
        RECT  28.692 21.563 28.71 21.6 ;
    END
  END b[176]
  PIN b[177]
    DIRECTION OUTPUT ;
    USE SIGNAL ;
    PORT
      LAYER M3 ;
        RECT  28.764 21.563 28.782 21.6 ;
    END
  END b[177]
  PIN b[178]
    DIRECTION OUTPUT ;
    USE SIGNAL ;
    PORT
      LAYER M3 ;
        RECT  28.836 21.563 28.854 21.6 ;
    END
  END b[178]
  PIN b[179]
    DIRECTION OUTPUT ;
    USE SIGNAL ;
    PORT
      LAYER M3 ;
        RECT  28.908 21.563 28.926 21.6 ;
    END
  END b[179]
  PIN b[17]
    DIRECTION OUTPUT ;
    USE SIGNAL ;
    PORT
      LAYER M5 ;
        RECT  29.616 21.516 29.64 21.6 ;
    END
  END b[17]
  PIN b[180]
    DIRECTION OUTPUT ;
    USE SIGNAL ;
    PORT
      LAYER M3 ;
        RECT  28.98 21.563 28.998 21.6 ;
    END
  END b[180]
  PIN b[181]
    DIRECTION OUTPUT ;
    USE SIGNAL ;
    PORT
      LAYER M3 ;
        RECT  29.052 21.563 29.07 21.6 ;
    END
  END b[181]
  PIN b[182]
    DIRECTION OUTPUT ;
    USE SIGNAL ;
    PORT
      LAYER M3 ;
        RECT  29.124 21.563 29.142 21.6 ;
    END
  END b[182]
  PIN b[183]
    DIRECTION OUTPUT ;
    USE SIGNAL ;
    PORT
      LAYER M3 ;
        RECT  29.196 21.563 29.214 21.6 ;
    END
  END b[183]
  PIN b[184]
    DIRECTION OUTPUT ;
    USE SIGNAL ;
    PORT
      LAYER M3 ;
        RECT  29.268 21.563 29.286 21.6 ;
    END
  END b[184]
  PIN b[185]
    DIRECTION OUTPUT ;
    USE SIGNAL ;
    PORT
      LAYER M3 ;
        RECT  29.34 21.563 29.358 21.6 ;
    END
  END b[185]
  PIN b[186]
    DIRECTION OUTPUT ;
    USE SIGNAL ;
    PORT
      LAYER M3 ;
        RECT  29.412 21.563 29.43 21.6 ;
    END
  END b[186]
  PIN b[187]
    DIRECTION OUTPUT ;
    USE SIGNAL ;
    PORT
      LAYER M3 ;
        RECT  29.484 21.563 29.502 21.6 ;
    END
  END b[187]
  PIN b[188]
    DIRECTION OUTPUT ;
    USE SIGNAL ;
    PORT
      LAYER M3 ;
        RECT  29.556 21.563 29.574 21.6 ;
    END
  END b[188]
  PIN b[189]
    DIRECTION OUTPUT ;
    USE SIGNAL ;
    PORT
      LAYER M3 ;
        RECT  29.628 21.563 29.646 21.6 ;
    END
  END b[189]
  PIN b[18]
    DIRECTION OUTPUT ;
    USE SIGNAL ;
    PORT
      LAYER M5 ;
        RECT  29.712 21.516 29.736 21.6 ;
    END
  END b[18]
  PIN b[190]
    DIRECTION OUTPUT ;
    USE SIGNAL ;
    PORT
      LAYER M3 ;
        RECT  29.7 21.563 29.718 21.6 ;
    END
  END b[190]
  PIN b[191]
    DIRECTION OUTPUT ;
    USE SIGNAL ;
    PORT
      LAYER M3 ;
        RECT  29.772 21.563 29.79 21.6 ;
    END
  END b[191]
  PIN b[192]
    DIRECTION OUTPUT ;
    USE SIGNAL ;
    PORT
      LAYER M5 ;
        RECT  24.912 21.516 24.936 21.6 ;
    END
  END b[192]
  PIN b[193]
    DIRECTION OUTPUT ;
    USE SIGNAL ;
    PORT
      LAYER M5 ;
        RECT  25.008 21.516 25.032 21.6 ;
    END
  END b[193]
  PIN b[194]
    DIRECTION OUTPUT ;
    USE SIGNAL ;
    PORT
      LAYER M5 ;
        RECT  25.104 21.516 25.128 21.6 ;
    END
  END b[194]
  PIN b[195]
    DIRECTION OUTPUT ;
    USE SIGNAL ;
    PORT
      LAYER M5 ;
        RECT  25.2 21.516 25.224 21.6 ;
    END
  END b[195]
  PIN b[196]
    DIRECTION OUTPUT ;
    USE SIGNAL ;
    PORT
      LAYER M5 ;
        RECT  25.296 21.516 25.32 21.6 ;
    END
  END b[196]
  PIN b[197]
    DIRECTION OUTPUT ;
    USE SIGNAL ;
    PORT
      LAYER M5 ;
        RECT  25.392 21.516 25.416 21.6 ;
    END
  END b[197]
  PIN b[198]
    DIRECTION OUTPUT ;
    USE SIGNAL ;
    PORT
      LAYER M5 ;
        RECT  25.488 21.516 25.512 21.6 ;
    END
  END b[198]
  PIN b[199]
    DIRECTION OUTPUT ;
    USE SIGNAL ;
    PORT
      LAYER M5 ;
        RECT  25.584 21.516 25.608 21.6 ;
    END
  END b[199]
  PIN b[19]
    DIRECTION OUTPUT ;
    USE SIGNAL ;
    PORT
      LAYER M5 ;
        RECT  29.808 21.516 29.832 21.6 ;
    END
  END b[19]
  PIN b[1]
    DIRECTION OUTPUT ;
    USE SIGNAL ;
    PORT
      LAYER M5 ;
        RECT  28.08 21.516 28.104 21.6 ;
    END
  END b[1]
  PIN b[200]
    DIRECTION OUTPUT ;
    USE SIGNAL ;
    PORT
      LAYER M5 ;
        RECT  25.68 21.516 25.704 21.6 ;
    END
  END b[200]
  PIN b[201]
    DIRECTION OUTPUT ;
    USE SIGNAL ;
    PORT
      LAYER M5 ;
        RECT  25.776 21.516 25.8 21.6 ;
    END
  END b[201]
  PIN b[202]
    DIRECTION OUTPUT ;
    USE SIGNAL ;
    PORT
      LAYER M5 ;
        RECT  25.872 21.516 25.896 21.6 ;
    END
  END b[202]
  PIN b[203]
    DIRECTION OUTPUT ;
    USE SIGNAL ;
    PORT
      LAYER M5 ;
        RECT  25.968 21.516 25.992 21.6 ;
    END
  END b[203]
  PIN b[204]
    DIRECTION OUTPUT ;
    USE SIGNAL ;
    PORT
      LAYER M5 ;
        RECT  26.064 21.516 26.088 21.6 ;
    END
  END b[204]
  PIN b[205]
    DIRECTION OUTPUT ;
    USE SIGNAL ;
    PORT
      LAYER M5 ;
        RECT  26.16 21.516 26.184 21.6 ;
    END
  END b[205]
  PIN b[206]
    DIRECTION OUTPUT ;
    USE SIGNAL ;
    PORT
      LAYER M5 ;
        RECT  26.256 21.516 26.28 21.6 ;
    END
  END b[206]
  PIN b[207]
    DIRECTION OUTPUT ;
    USE SIGNAL ;
    PORT
      LAYER M5 ;
        RECT  26.352 21.516 26.376 21.6 ;
    END
  END b[207]
  PIN b[208]
    DIRECTION OUTPUT ;
    USE SIGNAL ;
    PORT
      LAYER M5 ;
        RECT  26.448 21.516 26.472 21.6 ;
    END
  END b[208]
  PIN b[209]
    DIRECTION OUTPUT ;
    USE SIGNAL ;
    PORT
      LAYER M5 ;
        RECT  26.544 21.516 26.568 21.6 ;
    END
  END b[209]
  PIN b[20]
    DIRECTION OUTPUT ;
    USE SIGNAL ;
    PORT
      LAYER M5 ;
        RECT  29.904 21.516 29.928 21.6 ;
    END
  END b[20]
  PIN b[210]
    DIRECTION OUTPUT ;
    USE SIGNAL ;
    PORT
      LAYER M5 ;
        RECT  26.64 21.516 26.664 21.6 ;
    END
  END b[210]
  PIN b[211]
    DIRECTION OUTPUT ;
    USE SIGNAL ;
    PORT
      LAYER M5 ;
        RECT  26.736 21.516 26.76 21.6 ;
    END
  END b[211]
  PIN b[212]
    DIRECTION OUTPUT ;
    USE SIGNAL ;
    PORT
      LAYER M5 ;
        RECT  26.832 21.516 26.856 21.6 ;
    END
  END b[212]
  PIN b[213]
    DIRECTION OUTPUT ;
    USE SIGNAL ;
    PORT
      LAYER M5 ;
        RECT  26.928 21.516 26.952 21.6 ;
    END
  END b[213]
  PIN b[214]
    DIRECTION OUTPUT ;
    USE SIGNAL ;
    PORT
      LAYER M5 ;
        RECT  27.024 21.516 27.048 21.6 ;
    END
  END b[214]
  PIN b[215]
    DIRECTION OUTPUT ;
    USE SIGNAL ;
    PORT
      LAYER M5 ;
        RECT  27.12 21.516 27.144 21.6 ;
    END
  END b[215]
  PIN b[216]
    DIRECTION OUTPUT ;
    USE SIGNAL ;
    PORT
      LAYER M5 ;
        RECT  27.216 21.516 27.24 21.6 ;
    END
  END b[216]
  PIN b[217]
    DIRECTION OUTPUT ;
    USE SIGNAL ;
    PORT
      LAYER M5 ;
        RECT  27.312 21.516 27.336 21.6 ;
    END
  END b[217]
  PIN b[218]
    DIRECTION OUTPUT ;
    USE SIGNAL ;
    PORT
      LAYER M5 ;
        RECT  27.408 21.516 27.432 21.6 ;
    END
  END b[218]
  PIN b[219]
    DIRECTION OUTPUT ;
    USE SIGNAL ;
    PORT
      LAYER M5 ;
        RECT  27.504 21.516 27.528 21.6 ;
    END
  END b[219]
  PIN b[21]
    DIRECTION OUTPUT ;
    USE SIGNAL ;
    PORT
      LAYER M5 ;
        RECT  30 21.516 30.024 21.6 ;
    END
  END b[21]
  PIN b[220]
    DIRECTION OUTPUT ;
    USE SIGNAL ;
    PORT
      LAYER M5 ;
        RECT  27.6 21.516 27.624 21.6 ;
    END
  END b[220]
  PIN b[221]
    DIRECTION OUTPUT ;
    USE SIGNAL ;
    PORT
      LAYER M5 ;
        RECT  27.696 21.516 27.72 21.6 ;
    END
  END b[221]
  PIN b[222]
    DIRECTION OUTPUT ;
    USE SIGNAL ;
    PORT
      LAYER M5 ;
        RECT  27.792 21.516 27.816 21.6 ;
    END
  END b[222]
  PIN b[223]
    DIRECTION OUTPUT ;
    USE SIGNAL ;
    PORT
      LAYER M5 ;
        RECT  27.888 21.516 27.912 21.6 ;
    END
  END b[223]
  PIN b[224]
    DIRECTION OUTPUT ;
    USE SIGNAL ;
    PORT
      LAYER M5 ;
        RECT  21.84 21.516 21.864 21.6 ;
    END
  END b[224]
  PIN b[225]
    DIRECTION OUTPUT ;
    USE SIGNAL ;
    PORT
      LAYER M5 ;
        RECT  21.936 21.516 21.96 21.6 ;
    END
  END b[225]
  PIN b[226]
    DIRECTION OUTPUT ;
    USE SIGNAL ;
    PORT
      LAYER M5 ;
        RECT  22.032 21.516 22.056 21.6 ;
    END
  END b[226]
  PIN b[227]
    DIRECTION OUTPUT ;
    USE SIGNAL ;
    PORT
      LAYER M5 ;
        RECT  22.128 21.516 22.152 21.6 ;
    END
  END b[227]
  PIN b[228]
    DIRECTION OUTPUT ;
    USE SIGNAL ;
    PORT
      LAYER M5 ;
        RECT  22.224 21.516 22.248 21.6 ;
    END
  END b[228]
  PIN b[229]
    DIRECTION OUTPUT ;
    USE SIGNAL ;
    PORT
      LAYER M5 ;
        RECT  22.32 21.516 22.344 21.6 ;
    END
  END b[229]
  PIN b[22]
    DIRECTION OUTPUT ;
    USE SIGNAL ;
    PORT
      LAYER M5 ;
        RECT  30.096 21.516 30.12 21.6 ;
    END
  END b[22]
  PIN b[230]
    DIRECTION OUTPUT ;
    USE SIGNAL ;
    PORT
      LAYER M5 ;
        RECT  22.416 21.516 22.44 21.6 ;
    END
  END b[230]
  PIN b[231]
    DIRECTION OUTPUT ;
    USE SIGNAL ;
    PORT
      LAYER M5 ;
        RECT  22.512 21.516 22.536 21.6 ;
    END
  END b[231]
  PIN b[232]
    DIRECTION OUTPUT ;
    USE SIGNAL ;
    PORT
      LAYER M5 ;
        RECT  22.608 21.516 22.632 21.6 ;
    END
  END b[232]
  PIN b[233]
    DIRECTION OUTPUT ;
    USE SIGNAL ;
    PORT
      LAYER M5 ;
        RECT  22.704 21.516 22.728 21.6 ;
    END
  END b[233]
  PIN b[234]
    DIRECTION OUTPUT ;
    USE SIGNAL ;
    PORT
      LAYER M5 ;
        RECT  22.8 21.516 22.824 21.6 ;
    END
  END b[234]
  PIN b[235]
    DIRECTION OUTPUT ;
    USE SIGNAL ;
    PORT
      LAYER M5 ;
        RECT  22.896 21.516 22.92 21.6 ;
    END
  END b[235]
  PIN b[236]
    DIRECTION OUTPUT ;
    USE SIGNAL ;
    PORT
      LAYER M5 ;
        RECT  22.992 21.516 23.016 21.6 ;
    END
  END b[236]
  PIN b[237]
    DIRECTION OUTPUT ;
    USE SIGNAL ;
    PORT
      LAYER M5 ;
        RECT  23.088 21.516 23.112 21.6 ;
    END
  END b[237]
  PIN b[238]
    DIRECTION OUTPUT ;
    USE SIGNAL ;
    PORT
      LAYER M5 ;
        RECT  23.184 21.516 23.208 21.6 ;
    END
  END b[238]
  PIN b[239]
    DIRECTION OUTPUT ;
    USE SIGNAL ;
    PORT
      LAYER M5 ;
        RECT  23.28 21.516 23.304 21.6 ;
    END
  END b[239]
  PIN b[23]
    DIRECTION OUTPUT ;
    USE SIGNAL ;
    PORT
      LAYER M5 ;
        RECT  30.192 21.516 30.216 21.6 ;
    END
  END b[23]
  PIN b[240]
    DIRECTION OUTPUT ;
    USE SIGNAL ;
    PORT
      LAYER M5 ;
        RECT  23.376 21.516 23.4 21.6 ;
    END
  END b[240]
  PIN b[241]
    DIRECTION OUTPUT ;
    USE SIGNAL ;
    PORT
      LAYER M5 ;
        RECT  23.472 21.516 23.496 21.6 ;
    END
  END b[241]
  PIN b[242]
    DIRECTION OUTPUT ;
    USE SIGNAL ;
    PORT
      LAYER M5 ;
        RECT  23.568 21.516 23.592 21.6 ;
    END
  END b[242]
  PIN b[243]
    DIRECTION OUTPUT ;
    USE SIGNAL ;
    PORT
      LAYER M5 ;
        RECT  23.664 21.516 23.688 21.6 ;
    END
  END b[243]
  PIN b[244]
    DIRECTION OUTPUT ;
    USE SIGNAL ;
    PORT
      LAYER M5 ;
        RECT  23.76 21.516 23.784 21.6 ;
    END
  END b[244]
  PIN b[245]
    DIRECTION OUTPUT ;
    USE SIGNAL ;
    PORT
      LAYER M5 ;
        RECT  23.856 21.516 23.88 21.6 ;
    END
  END b[245]
  PIN b[246]
    DIRECTION OUTPUT ;
    USE SIGNAL ;
    PORT
      LAYER M5 ;
        RECT  23.952 21.516 23.976 21.6 ;
    END
  END b[246]
  PIN b[247]
    DIRECTION OUTPUT ;
    USE SIGNAL ;
    PORT
      LAYER M5 ;
        RECT  24.048 21.516 24.072 21.6 ;
    END
  END b[247]
  PIN b[248]
    DIRECTION OUTPUT ;
    USE SIGNAL ;
    PORT
      LAYER M5 ;
        RECT  24.144 21.516 24.168 21.6 ;
    END
  END b[248]
  PIN b[249]
    DIRECTION OUTPUT ;
    USE SIGNAL ;
    PORT
      LAYER M5 ;
        RECT  24.24 21.516 24.264 21.6 ;
    END
  END b[249]
  PIN b[24]
    DIRECTION OUTPUT ;
    USE SIGNAL ;
    PORT
      LAYER M5 ;
        RECT  30.288 21.516 30.312 21.6 ;
    END
  END b[24]
  PIN b[250]
    DIRECTION OUTPUT ;
    USE SIGNAL ;
    PORT
      LAYER M5 ;
        RECT  24.336 21.516 24.36 21.6 ;
    END
  END b[250]
  PIN b[251]
    DIRECTION OUTPUT ;
    USE SIGNAL ;
    PORT
      LAYER M5 ;
        RECT  24.432 21.516 24.456 21.6 ;
    END
  END b[251]
  PIN b[252]
    DIRECTION OUTPUT ;
    USE SIGNAL ;
    PORT
      LAYER M5 ;
        RECT  24.528 21.516 24.552 21.6 ;
    END
  END b[252]
  PIN b[253]
    DIRECTION OUTPUT ;
    USE SIGNAL ;
    PORT
      LAYER M5 ;
        RECT  24.624 21.516 24.648 21.6 ;
    END
  END b[253]
  PIN b[254]
    DIRECTION OUTPUT ;
    USE SIGNAL ;
    PORT
      LAYER M5 ;
        RECT  24.72 21.516 24.744 21.6 ;
    END
  END b[254]
  PIN b[255]
    DIRECTION OUTPUT ;
    USE SIGNAL ;
    PORT
      LAYER M5 ;
        RECT  24.816 21.516 24.84 21.6 ;
    END
  END b[255]
  PIN b[256]
    DIRECTION OUTPUT ;
    USE SIGNAL ;
    PORT
      LAYER M3 ;
        RECT  26.1 21.563 26.118 21.6 ;
    END
  END b[256]
  PIN b[257]
    DIRECTION OUTPUT ;
    USE SIGNAL ;
    PORT
      LAYER M3 ;
        RECT  26.172 21.563 26.19 21.6 ;
    END
  END b[257]
  PIN b[258]
    DIRECTION OUTPUT ;
    USE SIGNAL ;
    PORT
      LAYER M3 ;
        RECT  26.244 21.563 26.262 21.6 ;
    END
  END b[258]
  PIN b[259]
    DIRECTION OUTPUT ;
    USE SIGNAL ;
    PORT
      LAYER M3 ;
        RECT  26.316 21.563 26.334 21.6 ;
    END
  END b[259]
  PIN b[25]
    DIRECTION OUTPUT ;
    USE SIGNAL ;
    PORT
      LAYER M5 ;
        RECT  30.384 21.516 30.408 21.6 ;
    END
  END b[25]
  PIN b[260]
    DIRECTION OUTPUT ;
    USE SIGNAL ;
    PORT
      LAYER M3 ;
        RECT  26.388 21.563 26.406 21.6 ;
    END
  END b[260]
  PIN b[261]
    DIRECTION OUTPUT ;
    USE SIGNAL ;
    PORT
      LAYER M3 ;
        RECT  26.46 21.563 26.478 21.6 ;
    END
  END b[261]
  PIN b[262]
    DIRECTION OUTPUT ;
    USE SIGNAL ;
    PORT
      LAYER M3 ;
        RECT  26.532 21.563 26.55 21.6 ;
    END
  END b[262]
  PIN b[263]
    DIRECTION OUTPUT ;
    USE SIGNAL ;
    PORT
      LAYER M3 ;
        RECT  26.604 21.563 26.622 21.6 ;
    END
  END b[263]
  PIN b[264]
    DIRECTION OUTPUT ;
    USE SIGNAL ;
    PORT
      LAYER M3 ;
        RECT  26.676 21.563 26.694 21.6 ;
    END
  END b[264]
  PIN b[265]
    DIRECTION OUTPUT ;
    USE SIGNAL ;
    PORT
      LAYER M3 ;
        RECT  26.748 21.563 26.766 21.6 ;
    END
  END b[265]
  PIN b[266]
    DIRECTION OUTPUT ;
    USE SIGNAL ;
    PORT
      LAYER M3 ;
        RECT  26.82 21.563 26.838 21.6 ;
    END
  END b[266]
  PIN b[267]
    DIRECTION OUTPUT ;
    USE SIGNAL ;
    PORT
      LAYER M3 ;
        RECT  26.892 21.563 26.91 21.6 ;
    END
  END b[267]
  PIN b[268]
    DIRECTION OUTPUT ;
    USE SIGNAL ;
    PORT
      LAYER M3 ;
        RECT  26.964 21.563 26.982 21.6 ;
    END
  END b[268]
  PIN b[269]
    DIRECTION OUTPUT ;
    USE SIGNAL ;
    PORT
      LAYER M3 ;
        RECT  27.036 21.563 27.054 21.6 ;
    END
  END b[269]
  PIN b[26]
    DIRECTION OUTPUT ;
    USE SIGNAL ;
    PORT
      LAYER M5 ;
        RECT  30.48 21.516 30.504 21.6 ;
    END
  END b[26]
  PIN b[270]
    DIRECTION OUTPUT ;
    USE SIGNAL ;
    PORT
      LAYER M3 ;
        RECT  27.108 21.563 27.126 21.6 ;
    END
  END b[270]
  PIN b[271]
    DIRECTION OUTPUT ;
    USE SIGNAL ;
    PORT
      LAYER M3 ;
        RECT  27.18 21.563 27.198 21.6 ;
    END
  END b[271]
  PIN b[27]
    DIRECTION OUTPUT ;
    USE SIGNAL ;
    PORT
      LAYER M5 ;
        RECT  30.576 21.516 30.6 21.6 ;
    END
  END b[27]
  PIN b[28]
    DIRECTION OUTPUT ;
    USE SIGNAL ;
    PORT
      LAYER M5 ;
        RECT  30.672 21.516 30.696 21.6 ;
    END
  END b[28]
  PIN b[29]
    DIRECTION OUTPUT ;
    USE SIGNAL ;
    PORT
      LAYER M5 ;
        RECT  30.768 21.516 30.792 21.6 ;
    END
  END b[29]
  PIN b[2]
    DIRECTION OUTPUT ;
    USE SIGNAL ;
    PORT
      LAYER M5 ;
        RECT  28.176 21.516 28.2 21.6 ;
    END
  END b[2]
  PIN b[30]
    DIRECTION OUTPUT ;
    USE SIGNAL ;
    PORT
      LAYER M5 ;
        RECT  30.864 21.516 30.888 21.6 ;
    END
  END b[30]
  PIN b[31]
    DIRECTION OUTPUT ;
    USE SIGNAL ;
    PORT
      LAYER M5 ;
        RECT  30.96 21.516 30.984 21.6 ;
    END
  END b[31]
  PIN b[32]
    DIRECTION OUTPUT ;
    USE SIGNAL ;
    PORT
      LAYER M3 ;
        RECT  29.844 21.563 29.862 21.6 ;
    END
  END b[32]
  PIN b[33]
    DIRECTION OUTPUT ;
    USE SIGNAL ;
    PORT
      LAYER M3 ;
        RECT  29.916 21.563 29.934 21.6 ;
    END
  END b[33]
  PIN b[34]
    DIRECTION OUTPUT ;
    USE SIGNAL ;
    PORT
      LAYER M3 ;
        RECT  29.988 21.563 30.006 21.6 ;
    END
  END b[34]
  PIN b[35]
    DIRECTION OUTPUT ;
    USE SIGNAL ;
    PORT
      LAYER M3 ;
        RECT  30.06 21.563 30.078 21.6 ;
    END
  END b[35]
  PIN b[36]
    DIRECTION OUTPUT ;
    USE SIGNAL ;
    PORT
      LAYER M3 ;
        RECT  30.132 21.563 30.15 21.6 ;
    END
  END b[36]
  PIN b[37]
    DIRECTION OUTPUT ;
    USE SIGNAL ;
    PORT
      LAYER M3 ;
        RECT  30.204 21.563 30.222 21.6 ;
    END
  END b[37]
  PIN b[38]
    DIRECTION OUTPUT ;
    USE SIGNAL ;
    PORT
      LAYER M3 ;
        RECT  30.276 21.563 30.294 21.6 ;
    END
  END b[38]
  PIN b[39]
    DIRECTION OUTPUT ;
    USE SIGNAL ;
    PORT
      LAYER M3 ;
        RECT  30.348 21.563 30.366 21.6 ;
    END
  END b[39]
  PIN b[3]
    DIRECTION OUTPUT ;
    USE SIGNAL ;
    PORT
      LAYER M5 ;
        RECT  28.272 21.516 28.296 21.6 ;
    END
  END b[3]
  PIN b[40]
    DIRECTION OUTPUT ;
    USE SIGNAL ;
    PORT
      LAYER M3 ;
        RECT  30.42 21.563 30.438 21.6 ;
    END
  END b[40]
  PIN b[41]
    DIRECTION OUTPUT ;
    USE SIGNAL ;
    PORT
      LAYER M3 ;
        RECT  30.492 21.563 30.51 21.6 ;
    END
  END b[41]
  PIN b[42]
    DIRECTION OUTPUT ;
    USE SIGNAL ;
    PORT
      LAYER M3 ;
        RECT  30.564 21.563 30.582 21.6 ;
    END
  END b[42]
  PIN b[43]
    DIRECTION OUTPUT ;
    USE SIGNAL ;
    PORT
      LAYER M3 ;
        RECT  30.636 21.563 30.654 21.6 ;
    END
  END b[43]
  PIN b[44]
    DIRECTION OUTPUT ;
    USE SIGNAL ;
    PORT
      LAYER M3 ;
        RECT  30.708 21.563 30.726 21.6 ;
    END
  END b[44]
  PIN b[45]
    DIRECTION OUTPUT ;
    USE SIGNAL ;
    PORT
      LAYER M3 ;
        RECT  30.78 21.563 30.798 21.6 ;
    END
  END b[45]
  PIN b[46]
    DIRECTION OUTPUT ;
    USE SIGNAL ;
    PORT
      LAYER M3 ;
        RECT  30.852 21.563 30.87 21.6 ;
    END
  END b[46]
  PIN b[47]
    DIRECTION OUTPUT ;
    USE SIGNAL ;
    PORT
      LAYER M3 ;
        RECT  30.924 21.563 30.942 21.6 ;
    END
  END b[47]
  PIN b[48]
    DIRECTION OUTPUT ;
    USE SIGNAL ;
    PORT
      LAYER M3 ;
        RECT  30.996 21.563 31.014 21.6 ;
    END
  END b[48]
  PIN b[49]
    DIRECTION OUTPUT ;
    USE SIGNAL ;
    PORT
      LAYER M3 ;
        RECT  31.068 21.563 31.086 21.6 ;
    END
  END b[49]
  PIN b[4]
    DIRECTION OUTPUT ;
    USE SIGNAL ;
    PORT
      LAYER M5 ;
        RECT  28.368 21.516 28.392 21.6 ;
    END
  END b[4]
  PIN b[50]
    DIRECTION OUTPUT ;
    USE SIGNAL ;
    PORT
      LAYER M3 ;
        RECT  31.14 21.563 31.158 21.6 ;
    END
  END b[50]
  PIN b[51]
    DIRECTION OUTPUT ;
    USE SIGNAL ;
    PORT
      LAYER M3 ;
        RECT  31.212 21.563 31.23 21.6 ;
    END
  END b[51]
  PIN b[52]
    DIRECTION OUTPUT ;
    USE SIGNAL ;
    PORT
      LAYER M3 ;
        RECT  31.284 21.563 31.302 21.6 ;
    END
  END b[52]
  PIN b[53]
    DIRECTION OUTPUT ;
    USE SIGNAL ;
    PORT
      LAYER M3 ;
        RECT  31.356 21.563 31.374 21.6 ;
    END
  END b[53]
  PIN b[54]
    DIRECTION OUTPUT ;
    USE SIGNAL ;
    PORT
      LAYER M3 ;
        RECT  31.428 21.563 31.446 21.6 ;
    END
  END b[54]
  PIN b[55]
    DIRECTION OUTPUT ;
    USE SIGNAL ;
    PORT
      LAYER M3 ;
        RECT  31.5 21.563 31.518 21.6 ;
    END
  END b[55]
  PIN b[56]
    DIRECTION OUTPUT ;
    USE SIGNAL ;
    PORT
      LAYER M3 ;
        RECT  31.572 21.563 31.59 21.6 ;
    END
  END b[56]
  PIN b[57]
    DIRECTION OUTPUT ;
    USE SIGNAL ;
    PORT
      LAYER M3 ;
        RECT  31.644 21.563 31.662 21.6 ;
    END
  END b[57]
  PIN b[58]
    DIRECTION OUTPUT ;
    USE SIGNAL ;
    PORT
      LAYER M3 ;
        RECT  31.716 21.563 31.734 21.6 ;
    END
  END b[58]
  PIN b[59]
    DIRECTION OUTPUT ;
    USE SIGNAL ;
    PORT
      LAYER M3 ;
        RECT  31.788 21.563 31.806 21.6 ;
    END
  END b[59]
  PIN b[5]
    DIRECTION OUTPUT ;
    USE SIGNAL ;
    PORT
      LAYER M5 ;
        RECT  28.464 21.516 28.488 21.6 ;
    END
  END b[5]
  PIN b[60]
    DIRECTION OUTPUT ;
    USE SIGNAL ;
    PORT
      LAYER M3 ;
        RECT  31.86 21.563 31.878 21.6 ;
    END
  END b[60]
  PIN b[61]
    DIRECTION OUTPUT ;
    USE SIGNAL ;
    PORT
      LAYER M3 ;
        RECT  31.932 21.563 31.95 21.6 ;
    END
  END b[61]
  PIN b[62]
    DIRECTION OUTPUT ;
    USE SIGNAL ;
    PORT
      LAYER M3 ;
        RECT  32.004 21.563 32.022 21.6 ;
    END
  END b[62]
  PIN b[63]
    DIRECTION OUTPUT ;
    USE SIGNAL ;
    PORT
      LAYER M3 ;
        RECT  32.076 21.563 32.094 21.6 ;
    END
  END b[63]
  PIN b[64]
    DIRECTION OUTPUT ;
    USE SIGNAL ;
    PORT
      LAYER M5 ;
        RECT  18.768 21.516 18.792 21.6 ;
    END
  END b[64]
  PIN b[65]
    DIRECTION OUTPUT ;
    USE SIGNAL ;
    PORT
      LAYER M5 ;
        RECT  18.864 21.516 18.888 21.6 ;
    END
  END b[65]
  PIN b[66]
    DIRECTION OUTPUT ;
    USE SIGNAL ;
    PORT
      LAYER M5 ;
        RECT  18.96 21.516 18.984 21.6 ;
    END
  END b[66]
  PIN b[67]
    DIRECTION OUTPUT ;
    USE SIGNAL ;
    PORT
      LAYER M5 ;
        RECT  19.056 21.516 19.08 21.6 ;
    END
  END b[67]
  PIN b[68]
    DIRECTION OUTPUT ;
    USE SIGNAL ;
    PORT
      LAYER M5 ;
        RECT  19.152 21.516 19.176 21.6 ;
    END
  END b[68]
  PIN b[69]
    DIRECTION OUTPUT ;
    USE SIGNAL ;
    PORT
      LAYER M5 ;
        RECT  19.248 21.516 19.272 21.6 ;
    END
  END b[69]
  PIN b[6]
    DIRECTION OUTPUT ;
    USE SIGNAL ;
    PORT
      LAYER M5 ;
        RECT  28.56 21.516 28.584 21.6 ;
    END
  END b[6]
  PIN b[70]
    DIRECTION OUTPUT ;
    USE SIGNAL ;
    PORT
      LAYER M5 ;
        RECT  19.344 21.516 19.368 21.6 ;
    END
  END b[70]
  PIN b[71]
    DIRECTION OUTPUT ;
    USE SIGNAL ;
    PORT
      LAYER M5 ;
        RECT  19.44 21.516 19.464 21.6 ;
    END
  END b[71]
  PIN b[72]
    DIRECTION OUTPUT ;
    USE SIGNAL ;
    PORT
      LAYER M5 ;
        RECT  19.536 21.516 19.56 21.6 ;
    END
  END b[72]
  PIN b[73]
    DIRECTION OUTPUT ;
    USE SIGNAL ;
    PORT
      LAYER M5 ;
        RECT  19.632 21.516 19.656 21.6 ;
    END
  END b[73]
  PIN b[74]
    DIRECTION OUTPUT ;
    USE SIGNAL ;
    PORT
      LAYER M5 ;
        RECT  19.728 21.516 19.752 21.6 ;
    END
  END b[74]
  PIN b[75]
    DIRECTION OUTPUT ;
    USE SIGNAL ;
    PORT
      LAYER M5 ;
        RECT  19.824 21.516 19.848 21.6 ;
    END
  END b[75]
  PIN b[76]
    DIRECTION OUTPUT ;
    USE SIGNAL ;
    PORT
      LAYER M5 ;
        RECT  19.92 21.516 19.944 21.6 ;
    END
  END b[76]
  PIN b[77]
    DIRECTION OUTPUT ;
    USE SIGNAL ;
    PORT
      LAYER M5 ;
        RECT  20.016 21.516 20.04 21.6 ;
    END
  END b[77]
  PIN b[78]
    DIRECTION OUTPUT ;
    USE SIGNAL ;
    PORT
      LAYER M5 ;
        RECT  20.112 21.516 20.136 21.6 ;
    END
  END b[78]
  PIN b[79]
    DIRECTION OUTPUT ;
    USE SIGNAL ;
    PORT
      LAYER M5 ;
        RECT  20.208 21.516 20.232 21.6 ;
    END
  END b[79]
  PIN b[7]
    DIRECTION OUTPUT ;
    USE SIGNAL ;
    PORT
      LAYER M5 ;
        RECT  28.656 21.516 28.68 21.6 ;
    END
  END b[7]
  PIN b[80]
    DIRECTION OUTPUT ;
    USE SIGNAL ;
    PORT
      LAYER M5 ;
        RECT  20.304 21.516 20.328 21.6 ;
    END
  END b[80]
  PIN b[81]
    DIRECTION OUTPUT ;
    USE SIGNAL ;
    PORT
      LAYER M5 ;
        RECT  20.4 21.516 20.424 21.6 ;
    END
  END b[81]
  PIN b[82]
    DIRECTION OUTPUT ;
    USE SIGNAL ;
    PORT
      LAYER M5 ;
        RECT  20.496 21.516 20.52 21.6 ;
    END
  END b[82]
  PIN b[83]
    DIRECTION OUTPUT ;
    USE SIGNAL ;
    PORT
      LAYER M5 ;
        RECT  20.592 21.516 20.616 21.6 ;
    END
  END b[83]
  PIN b[84]
    DIRECTION OUTPUT ;
    USE SIGNAL ;
    PORT
      LAYER M5 ;
        RECT  20.688 21.516 20.712 21.6 ;
    END
  END b[84]
  PIN b[85]
    DIRECTION OUTPUT ;
    USE SIGNAL ;
    PORT
      LAYER M5 ;
        RECT  20.784 21.516 20.808 21.6 ;
    END
  END b[85]
  PIN b[86]
    DIRECTION OUTPUT ;
    USE SIGNAL ;
    PORT
      LAYER M5 ;
        RECT  20.88 21.516 20.904 21.6 ;
    END
  END b[86]
  PIN b[87]
    DIRECTION OUTPUT ;
    USE SIGNAL ;
    PORT
      LAYER M5 ;
        RECT  20.976 21.516 21 21.6 ;
    END
  END b[87]
  PIN b[88]
    DIRECTION OUTPUT ;
    USE SIGNAL ;
    PORT
      LAYER M5 ;
        RECT  21.072 21.516 21.096 21.6 ;
    END
  END b[88]
  PIN b[89]
    DIRECTION OUTPUT ;
    USE SIGNAL ;
    PORT
      LAYER M5 ;
        RECT  21.168 21.516 21.192 21.6 ;
    END
  END b[89]
  PIN b[8]
    DIRECTION OUTPUT ;
    USE SIGNAL ;
    PORT
      LAYER M5 ;
        RECT  28.752 21.516 28.776 21.6 ;
    END
  END b[8]
  PIN b[90]
    DIRECTION OUTPUT ;
    USE SIGNAL ;
    PORT
      LAYER M5 ;
        RECT  21.264 21.516 21.288 21.6 ;
    END
  END b[90]
  PIN b[91]
    DIRECTION OUTPUT ;
    USE SIGNAL ;
    PORT
      LAYER M5 ;
        RECT  21.36 21.516 21.384 21.6 ;
    END
  END b[91]
  PIN b[92]
    DIRECTION OUTPUT ;
    USE SIGNAL ;
    PORT
      LAYER M5 ;
        RECT  21.456 21.516 21.48 21.6 ;
    END
  END b[92]
  PIN b[93]
    DIRECTION OUTPUT ;
    USE SIGNAL ;
    PORT
      LAYER M5 ;
        RECT  21.552 21.516 21.576 21.6 ;
    END
  END b[93]
  PIN b[94]
    DIRECTION OUTPUT ;
    USE SIGNAL ;
    PORT
      LAYER M5 ;
        RECT  21.648 21.516 21.672 21.6 ;
    END
  END b[94]
  PIN b[95]
    DIRECTION OUTPUT ;
    USE SIGNAL ;
    PORT
      LAYER M5 ;
        RECT  21.744 21.516 21.768 21.6 ;
    END
  END b[95]
  PIN b[96]
    DIRECTION OUTPUT ;
    USE SIGNAL ;
    PORT
      LAYER M5 ;
        RECT  15.696 21.516 15.72 21.6 ;
    END
  END b[96]
  PIN b[97]
    DIRECTION OUTPUT ;
    USE SIGNAL ;
    PORT
      LAYER M5 ;
        RECT  15.792 21.516 15.816 21.6 ;
    END
  END b[97]
  PIN b[98]
    DIRECTION OUTPUT ;
    USE SIGNAL ;
    PORT
      LAYER M5 ;
        RECT  15.888 21.516 15.912 21.6 ;
    END
  END b[98]
  PIN b[99]
    DIRECTION OUTPUT ;
    USE SIGNAL ;
    PORT
      LAYER M5 ;
        RECT  15.984 21.516 16.008 21.6 ;
    END
  END b[99]
  PIN b[9]
    DIRECTION OUTPUT ;
    USE SIGNAL ;
    PORT
      LAYER M5 ;
        RECT  28.848 21.516 28.872 21.6 ;
    END
  END b[9]
  PIN ck_o[0]
    DIRECTION OUTPUT ;
    USE SIGNAL ;
    PORT
      LAYER M3 ;
        RECT  27.252 21.563 27.27 21.6 ;
    END
  END ck_o[0]
  PIN ck_o[1]
    DIRECTION OUTPUT ;
    USE SIGNAL ;
    PORT
      LAYER M3 ;
        RECT  27.324 21.563 27.342 21.6 ;
    END
  END ck_o[1]
  PIN ckf
    DIRECTION INPUT ;
    USE SIGNAL ;
    PORT
      LAYER M5 ;
        RECT  23.76 0 23.784 0.084 ;
    END
  END ckf
  PIN ea
    DIRECTION INPUT ;
    USE SIGNAL ;
    PORT
      LAYER M5 ;
        RECT  23.856 0 23.88 0.084 ;
    END
  END ea
  PIN eb[0]
    DIRECTION OUTPUT ;
    USE SIGNAL ;
    PORT
      LAYER M3 ;
        RECT  27.396 21.563 27.414 21.6 ;
    END
  END eb[0]
  PIN eb[1]
    DIRECTION OUTPUT ;
    USE SIGNAL ;
    PORT
      LAYER M3 ;
        RECT  27.468 21.563 27.486 21.6 ;
    END
  END eb[1]
  PIN VDD
    DIRECTION INOUT ;
    USE POWER ;
    PORT
      LAYER M5 ;
        RECT  51.192 2.151 51.312 19.449 ;
        RECT  48.492 2.151 48.612 19.449 ;
        RECT  45.792 2.151 45.912 19.449 ;
        RECT  43.092 2.151 43.212 19.449 ;
        RECT  40.392 2.151 40.512 19.449 ;
        RECT  37.692 2.151 37.812 19.449 ;
        RECT  34.992 2.151 35.112 19.449 ;
        RECT  32.292 2.151 32.412 19.449 ;
        RECT  29.592 2.151 29.712 19.449 ;
        RECT  26.892 2.151 27.012 19.449 ;
        RECT  24.192 2.151 24.312 19.449 ;
        RECT  21.492 2.151 21.612 19.449 ;
        RECT  18.792 2.151 18.912 19.449 ;
        RECT  16.092 2.151 16.212 19.449 ;
        RECT  13.392 2.151 13.512 19.449 ;
        RECT  10.692 2.151 10.812 19.449 ;
        RECT  7.992 2.151 8.112 19.449 ;
        RECT  5.292 2.151 5.412 19.449 ;
        RECT  2.592 2.151 2.712 19.449 ;
    END
  END VDD
  PIN VSS
    DIRECTION INOUT ;
    USE GROUND ;
    PORT
      LAYER M5 ;
        RECT  51 2.137 51.12 19.463 ;
        RECT  48.3 2.137 48.42 19.463 ;
        RECT  45.6 2.137 45.72 19.463 ;
        RECT  42.9 2.137 43.02 19.463 ;
        RECT  40.2 2.137 40.32 19.463 ;
        RECT  37.5 2.137 37.62 19.463 ;
        RECT  34.8 2.137 34.92 19.463 ;
        RECT  32.1 2.137 32.22 19.463 ;
        RECT  29.4 2.137 29.52 19.463 ;
        RECT  26.7 2.137 26.82 19.463 ;
        RECT  24 2.137 24.12 19.463 ;
        RECT  21.3 2.137 21.42 19.463 ;
        RECT  18.6 2.137 18.72 19.463 ;
        RECT  15.9 2.137 16.02 19.463 ;
        RECT  13.2 2.137 13.32 19.463 ;
        RECT  10.5 2.137 10.62 19.463 ;
        RECT  7.8 2.137 7.92 19.463 ;
        RECT  5.1 2.137 5.22 19.463 ;
        RECT  2.4 2.137 2.52 19.463 ;
    END
  END VSS
  # OT_OBS_CLOSED layer=M5 d_um=1.536 added=27
  OBS
    LAYER RVTN ;
     RECT  2.16 2.16 51.84 2.295 ;
     RECT  2.16 2.565 51.84 2.835 ;
     RECT  2.16 3.105 51.84 3.375 ;
     RECT  2.16 3.645 51.84 3.915 ;
     RECT  2.16 4.185 51.84 4.455 ;
     RECT  2.16 4.725 51.84 4.995 ;
     RECT  2.16 5.265 51.84 5.535 ;
     RECT  2.16 5.805 51.84 6.075 ;
     RECT  2.16 6.345 51.84 6.615 ;
     RECT  2.16 6.885 51.84 7.155 ;
     RECT  2.16 7.425 51.84 7.695 ;
     RECT  2.16 7.965 51.84 8.235 ;
     RECT  2.16 8.505 51.84 8.775 ;
     RECT  2.16 9.045 51.84 9.315 ;
     RECT  2.16 9.585 51.84 9.855 ;
     RECT  2.16 10.125 51.84 10.395 ;
     RECT  2.16 10.665 51.84 10.935 ;
     RECT  2.16 11.205 51.84 11.475 ;
     RECT  2.16 11.745 51.84 12.015 ;
     RECT  2.16 12.285 51.84 12.555 ;
     RECT  2.16 12.825 51.84 13.095 ;
     RECT  2.16 13.365 51.84 13.635 ;
     RECT  2.16 13.905 51.84 14.175 ;
     RECT  2.16 14.445 51.84 14.715 ;
     RECT  2.16 14.985 51.84 15.255 ;
     RECT  2.16 15.525 51.84 15.795 ;
     RECT  2.16 16.065 51.84 16.335 ;
     RECT  2.16 16.605 51.84 16.875 ;
     RECT  2.16 17.145 51.84 17.415 ;
     RECT  2.16 17.685 51.84 17.955 ;
     RECT  2.16 18.225 51.84 18.495 ;
     RECT  2.16 18.765 51.84 19.035 ;
     RECT  2.16 19.305 51.84 19.44 ;
    LAYER RVTP ;
     RECT  2.16 2.295 51.84 2.565 ;
     RECT  2.16 2.835 51.84 3.105 ;
     RECT  2.16 3.375 51.84 3.645 ;
     RECT  2.16 3.915 51.84 4.185 ;
     RECT  2.16 4.455 51.84 4.725 ;
     RECT  2.16 4.995 51.84 5.265 ;
     RECT  2.16 5.535 51.84 5.805 ;
     RECT  2.16 6.075 51.84 6.345 ;
     RECT  2.16 6.615 51.84 6.885 ;
     RECT  2.16 7.155 51.84 7.425 ;
     RECT  2.16 7.695 51.84 7.965 ;
     RECT  2.16 8.235 51.84 8.505 ;
     RECT  2.16 8.775 51.84 9.045 ;
     RECT  2.16 9.315 51.84 9.585 ;
     RECT  2.16 9.855 51.84 10.125 ;
     RECT  2.16 10.395 51.84 10.665 ;
     RECT  2.16 10.935 51.84 11.205 ;
     RECT  2.16 11.475 51.84 11.745 ;
     RECT  2.16 12.015 51.84 12.285 ;
     RECT  2.16 12.555 51.84 12.825 ;
     RECT  2.16 13.095 51.84 13.365 ;
     RECT  2.16 13.635 51.84 13.905 ;
     RECT  2.16 14.175 51.84 14.445 ;
     RECT  2.16 14.715 51.84 14.985 ;
     RECT  2.16 15.255 51.84 15.525 ;
     RECT  2.16 15.795 51.84 16.065 ;
     RECT  2.16 16.335 51.84 16.605 ;
     RECT  2.16 16.875 51.84 17.145 ;
     RECT  2.16 17.415 51.84 17.685 ;
     RECT  2.16 17.955 51.84 18.225 ;
     RECT  2.16 18.495 51.84 18.765 ;
     RECT  2.16 19.035 51.84 19.305 ;
    LAYER M1 ;
     RECT  2.16 2.151 51.84 19.449 ;
    LAYER M2 ;
     RECT  2.16 2.151 18.067 19.449 ;
     RECT  18.067 2.151 18.211 19.494 ;
     RECT  18.211 2.151 18.859 19.53 ;
     RECT  18.859 2.151 18.931 19.638 ;
     RECT  18.931 2.151 21.523 19.719 ;
     RECT  21.523 1.926 21.703 19.719 ;
     RECT  21.667 0.954 21.883 0.972 ;
     RECT  21.883 0.954 21.919 1.008 ;
     RECT  21.919 0.882 22.171 1.008 ;
     RECT  22.171 0.846 22.199 1.008 ;
     RECT  21.703 1.836 22.459 19.719 ;
     RECT  22.459 1.8 22.747 19.719 ;
     RECT  22.199 0.846 22.999 0.972 ;
     RECT  22.999 0.576 23.935 0.972 ;
     RECT  22.747 1.728 23.935 19.719 ;
     RECT  23.935 0.576 24.259 19.719 ;
     RECT  24.259 0.036 24.287 19.719 ;
     RECT  24.287 1.728 24.683 19.719 ;
     RECT  24.683 1.728 24.719 19.494 ;
     RECT  24.287 0.036 25.331 0.972 ;
     RECT  25.331 0.036 26.123 0.9 ;
     RECT  26.123 0.036 26.519 0.774 ;
     RECT  26.491 21.474 26.527 21.492 ;
     RECT  24.719 1.728 26.555 19.449 ;
     RECT  26.527 21.474 26.563 21.564 ;
     RECT  26.563 21.402 26.699 21.564 ;
     RECT  25.699 20.511 26.771 20.529 ;
     RECT  26.555 1.926 26.815 19.449 ;
     RECT  26.815 1.926 27.103 19.53 ;
     RECT  26.699 21.474 27.203 21.564 ;
     RECT  27.103 1.926 27.311 19.566 ;
     RECT  27.203 21.546 27.311 21.564 ;
     RECT  26.519 0.036 27.607 0.36 ;
     RECT  27.607 0.036 27.643 0.594 ;
     RECT  27.643 0.036 28.075 1.17 ;
     RECT  28.075 0.036 28.147 1.206 ;
     RECT  27.311 2.106 28.355 19.449 ;
     RECT  28.147 0.036 28.391 1.359 ;
     RECT  28.391 0.036 28.499 1.278 ;
     RECT  28.499 0.036 28.823 0.594 ;
     RECT  28.823 0.036 28.859 0.054 ;
     RECT  28.355 2.151 29.191 19.449 ;
     RECT  28.867 21.546 29.191 21.564 ;
     RECT  29.191 21.402 29.407 21.564 ;
     RECT  29.443 20.511 29.479 20.529 ;
     RECT  29.191 2.151 29.515 19.494 ;
     RECT  29.479 20.466 29.695 20.529 ;
     RECT  29.695 20.394 30.487 20.529 ;
     RECT  30.487 20.394 30.623 20.574 ;
     RECT  29.515 2.151 30.775 19.53 ;
     RECT  30.623 20.394 30.947 20.412 ;
     RECT  29.407 21.366 31.019 21.564 ;
     RECT  30.775 2.034 31.343 19.53 ;
     RECT  31.343 2.034 31.567 19.494 ;
     RECT  31.567 1.962 31.703 19.494 ;
     RECT  31.019 21.402 32.063 21.564 ;
     RECT  32.063 21.474 32.099 21.564 ;
     RECT  32.099 21.546 32.315 21.564 ;
     RECT  31.703 1.962 33.395 19.449 ;
     RECT  33.395 2.151 51.84 19.449 ;
    LAYER M3 ;
     RECT  24.174 0.012 24.228 0.031 ;
     RECT  24.246 0.012 24.3 0.031 ;
     RECT  24.318 0.012 24.372 0.031 ;
     RECT  24.39 0.012 24.444 0.031 ;
     RECT  24.462 0.012 24.516 0.031 ;
     RECT  24.534 0.012 24.588 0.031 ;
     RECT  24.606 0.012 24.66 0.031 ;
     RECT  24.678 0.012 24.732 0.031 ;
     RECT  24.75 0.012 24.804 0.031 ;
     RECT  24.822 0.012 24.876 0.031 ;
     RECT  24.894 0.012 24.948 0.031 ;
     RECT  24.966 0.012 25.02 0.031 ;
     RECT  25.038 0.012 25.092 0.031 ;
     RECT  25.11 0.012 25.164 0.031 ;
     RECT  25.182 0.012 25.236 0.031 ;
     RECT  25.254 0.012 25.308 0.031 ;
     RECT  25.326 0.012 25.38 0.031 ;
     RECT  25.398 0.012 25.452 0.031 ;
     RECT  25.47 0.012 25.524 0.031 ;
     RECT  25.542 0.012 25.596 0.031 ;
     RECT  25.614 0.012 25.668 0.031 ;
     RECT  25.686 0.012 25.74 0.031 ;
     RECT  25.758 0.012 25.812 0.031 ;
     RECT  25.83 0.012 25.884 0.031 ;
     RECT  25.902 0.012 25.956 0.031 ;
     RECT  25.974 0.012 26.028 0.031 ;
     RECT  26.046 0.012 26.1 0.031 ;
     RECT  26.118 0.012 26.172 0.031 ;
     RECT  26.19 0.012 26.244 0.031 ;
     RECT  26.262 0.012 26.316 0.031 ;
     RECT  26.334 0.012 26.388 0.031 ;
     RECT  26.406 0.012 26.46 0.031 ;
     RECT  26.478 0.012 26.532 0.031 ;
     RECT  26.55 0.012 26.604 0.031 ;
     RECT  26.622 0.012 26.676 0.031 ;
     RECT  26.694 0.012 26.748 0.031 ;
     RECT  26.766 0.012 26.82 0.031 ;
     RECT  26.838 0.012 26.892 0.031 ;
     RECT  26.91 0.012 26.964 0.031 ;
     RECT  26.982 0.012 27.036 0.031 ;
     RECT  27.054 0.012 27.108 0.031 ;
     RECT  27.126 0.012 27.18 0.031 ;
     RECT  27.198 0.012 27.252 0.031 ;
     RECT  27.27 0.012 27.324 0.031 ;
     RECT  27.342 0.012 27.396 0.031 ;
     RECT  27.414 0.012 27.468 0.031 ;
     RECT  27.486 0.012 27.54 0.031 ;
     RECT  27.558 0.012 27.612 0.031 ;
     RECT  27.63 0.012 27.684 0.031 ;
     RECT  27.702 0.012 27.756 0.031 ;
     RECT  27.774 0.012 27.828 0.031 ;
     RECT  27.846 0.012 27.9 0.031 ;
     RECT  27.918 0.012 27.972 0.031 ;
     RECT  27.99 0.012 28.044 0.031 ;
     RECT  28.062 0.012 28.116 0.031 ;
     RECT  28.134 0.012 28.188 0.031 ;
     RECT  28.206 0.012 28.26 0.031 ;
     RECT  28.278 0.012 28.332 0.031 ;
     RECT  28.35 0.012 28.404 0.031 ;
     RECT  28.422 0.012 28.476 0.031 ;
     RECT  28.494 0.012 28.548 0.031 ;
     RECT  28.566 0.012 28.62 0.031 ;
     RECT  28.638 0.012 28.692 0.031 ;
     RECT  24.174 0.031 24.228 0.037 ;
     RECT  24.246 0.031 24.3 0.037 ;
     RECT  24.318 0.031 24.372 0.037 ;
     RECT  24.39 0.031 24.444 0.037 ;
     RECT  24.462 0.031 24.516 0.037 ;
     RECT  24.534 0.031 24.588 0.037 ;
     RECT  24.606 0.031 24.66 0.037 ;
     RECT  24.678 0.031 24.732 0.037 ;
     RECT  24.75 0.031 24.804 0.037 ;
     RECT  24.822 0.031 24.876 0.037 ;
     RECT  24.894 0.031 24.948 0.037 ;
     RECT  24.966 0.031 25.02 0.037 ;
     RECT  25.038 0.031 25.092 0.037 ;
     RECT  25.11 0.031 25.164 0.037 ;
     RECT  25.182 0.031 25.236 0.037 ;
     RECT  25.254 0.031 25.308 0.037 ;
     RECT  25.326 0.031 25.38 0.037 ;
     RECT  25.398 0.031 25.452 0.037 ;
     RECT  25.47 0.031 25.524 0.037 ;
     RECT  25.542 0.031 25.596 0.037 ;
     RECT  25.614 0.031 25.668 0.037 ;
     RECT  25.686 0.031 25.74 0.037 ;
     RECT  25.758 0.031 25.812 0.037 ;
     RECT  25.83 0.031 25.884 0.037 ;
     RECT  25.902 0.031 25.956 0.037 ;
     RECT  25.974 0.031 26.028 0.037 ;
     RECT  26.046 0.031 26.1 0.037 ;
     RECT  26.118 0.031 26.172 0.037 ;
     RECT  26.19 0.031 26.244 0.037 ;
     RECT  26.262 0.031 26.316 0.037 ;
     RECT  26.334 0.031 26.388 0.037 ;
     RECT  26.406 0.031 26.46 0.037 ;
     RECT  26.478 0.031 26.532 0.037 ;
     RECT  26.55 0.031 26.604 0.037 ;
     RECT  26.622 0.031 26.676 0.037 ;
     RECT  26.694 0.031 26.748 0.037 ;
     RECT  26.766 0.031 26.82 0.037 ;
     RECT  26.838 0.031 26.892 0.037 ;
     RECT  26.91 0.031 26.964 0.037 ;
     RECT  26.982 0.031 27.036 0.037 ;
     RECT  27.054 0.031 27.108 0.037 ;
     RECT  27.126 0.031 27.18 0.037 ;
     RECT  27.198 0.031 27.252 0.037 ;
     RECT  27.27 0.031 27.324 0.037 ;
     RECT  27.342 0.031 27.396 0.037 ;
     RECT  27.414 0.031 27.468 0.037 ;
     RECT  27.486 0.031 27.54 0.037 ;
     RECT  27.558 0.031 27.612 0.037 ;
     RECT  27.63 0.031 27.684 0.037 ;
     RECT  27.702 0.031 27.756 0.037 ;
     RECT  27.774 0.031 27.828 0.037 ;
     RECT  27.846 0.031 27.9 0.037 ;
     RECT  27.918 0.031 27.972 0.037 ;
     RECT  27.99 0.031 28.044 0.037 ;
     RECT  28.062 0.031 28.116 0.037 ;
     RECT  28.134 0.031 28.188 0.037 ;
     RECT  28.206 0.031 28.26 0.037 ;
     RECT  28.278 0.031 28.332 0.037 ;
     RECT  28.35 0.031 28.404 0.037 ;
     RECT  28.422 0.031 28.476 0.037 ;
     RECT  28.494 0.031 28.548 0.037 ;
     RECT  28.566 0.031 28.62 0.037 ;
     RECT  28.638 0.031 28.692 0.037 ;
     RECT  28.71 0.031 28.854 0.037 ;
     RECT  24.156 0.037 28.854 0.043 ;
     RECT  24.156 0.043 28.89 0.091 ;
     RECT  23.652 0.091 28.89 0.173 ;
     RECT  29.88 0.091 30.186 0.187 ;
     RECT  30.924 0.091 31.266 0.269 ;
     RECT  29.808 0.187 30.186 0.317 ;
     RECT  31.068 0.269 31.266 0.317 ;
     RECT  29.808 0.317 30.042 0.365 ;
     RECT  31.248 0.317 31.266 0.365 ;
     RECT  30.024 0.365 30.042 0.413 ;
     RECT  23.652 0.173 28.854 0.571 ;
     RECT  34.164 0.043 34.182 0.571 ;
     RECT  22.212 0.091 22.23 0.841 ;
     RECT  32.976 0.811 32.994 0.859 ;
     RECT  22.176 0.841 22.23 0.877 ;
     RECT  32.508 0.859 32.994 0.907 ;
     RECT  21.924 0.877 22.23 0.949 ;
     RECT  21.672 0.949 22.23 1.723 ;
     RECT  23.004 0.571 28.854 1.723 ;
     RECT  32.076 0.907 32.994 1.723 ;
     RECT  33.84 0.571 34.182 1.723 ;
     RECT  31.356 1.723 34.182 1.771 ;
     RECT  21.672 1.723 29.07 1.921 ;
     RECT  21.528 1.921 29.07 2.011 ;
     RECT  31.212 1.771 34.182 2.029 ;
     RECT  21.528 2.011 29.574 2.143 ;
     RECT  30.78 2.029 34.182 2.143 ;
     RECT  21.315 2.143 29.574 2.191 ;
     RECT  21.315 2.191 29.97 2.299 ;
     RECT  21.132 2.299 29.97 2.335 ;
     RECT  30.78 2.143 34.905 2.335 ;
     RECT  2.415 2.143 2.505 2.413 ;
     RECT  5.115 2.143 5.205 2.413 ;
     RECT  7.815 2.143 7.905 2.413 ;
     RECT  10.515 2.143 10.605 2.413 ;
     RECT  13.215 2.143 13.305 2.413 ;
     RECT  15.915 2.143 16.005 2.413 ;
     RECT  18.615 2.143 18.705 2.413 ;
     RECT  21.132 2.335 34.905 2.413 ;
     RECT  37.515 2.143 37.605 2.413 ;
     RECT  40.215 2.143 40.305 2.413 ;
     RECT  42.915 2.143 43.005 2.413 ;
     RECT  45.615 2.143 45.705 2.413 ;
     RECT  48.315 2.143 48.405 2.413 ;
     RECT  51.015 2.143 51.105 2.413 ;
     RECT  21.132 2.413 35.097 2.875 ;
     RECT  21.096 2.875 35.097 3.181 ;
     RECT  20.7 3.181 35.097 3.335 ;
     RECT  21.315 3.335 35.097 17.249 ;
     RECT  18.615 2.413 18.897 17.419 ;
     RECT  21.315 17.249 33.21 17.467 ;
     RECT  21.024 17.467 33.21 17.491 ;
     RECT  34.308 17.249 35.097 17.609 ;
     RECT  18.615 17.419 18.954 17.659 ;
     RECT  34.452 17.609 35.097 17.681 ;
     RECT  18.615 17.659 19.062 17.725 ;
     RECT  18.072 17.725 19.062 17.851 ;
     RECT  19.872 17.761 19.962 17.851 ;
     RECT  20.7 17.491 33.21 17.851 ;
     RECT  17.028 17.581 17.046 18.031 ;
     RECT  15.915 2.413 16.197 18.121 ;
     RECT  16.956 18.031 17.046 18.121 ;
     RECT  17.964 17.851 33.21 18.301 ;
     RECT  15.915 18.121 17.046 18.391 ;
     RECT  17.964 18.301 33.318 18.391 ;
     RECT  15.915 18.391 33.318 18.661 ;
     RECT  2.415 2.413 2.697 19.187 ;
     RECT  5.115 2.413 5.397 19.187 ;
     RECT  7.815 2.413 8.097 19.187 ;
     RECT  10.515 2.413 10.797 19.187 ;
     RECT  13.215 2.413 13.497 19.187 ;
     RECT  34.815 17.681 35.097 19.187 ;
     RECT  37.515 2.413 37.797 19.187 ;
     RECT  40.215 2.413 40.497 19.187 ;
     RECT  42.915 2.413 43.197 19.187 ;
     RECT  45.615 2.413 45.897 19.187 ;
     RECT  48.315 2.413 48.597 19.187 ;
     RECT  51.015 2.413 51.297 19.187 ;
     RECT  15.915 18.661 33.714 19.201 ;
     RECT  15.915 19.201 33.93 19.309 ;
     RECT  15.732 19.309 33.93 19.373 ;
     RECT  15.915 19.373 33.93 19.409 ;
     RECT  2.415 19.187 2.505 19.457 ;
     RECT  5.115 19.187 5.205 19.457 ;
     RECT  7.815 19.187 7.905 19.457 ;
     RECT  10.515 19.187 10.605 19.457 ;
     RECT  13.215 19.187 13.305 19.457 ;
     RECT  15.915 19.409 16.506 19.457 ;
     RECT  34.815 19.187 34.905 19.457 ;
     RECT  37.515 19.187 37.605 19.457 ;
     RECT  40.215 19.187 40.305 19.457 ;
     RECT  42.915 19.187 43.005 19.457 ;
     RECT  45.615 19.187 45.705 19.457 ;
     RECT  48.315 19.187 48.405 19.457 ;
     RECT  51.015 19.187 51.105 19.457 ;
     RECT  16.092 19.457 16.506 19.565 ;
     RECT  16.236 19.565 16.398 19.613 ;
     RECT  16.344 19.613 16.398 19.661 ;
     RECT  17.568 19.409 33.93 19.709 ;
     RECT  17.568 19.709 19.71 19.757 ;
     RECT  20.556 19.709 33.93 19.949 ;
     RECT  21.672 19.949 33.93 19.997 ;
     RECT  19.08 19.757 19.71 20.237 ;
     RECT  20.556 19.949 20.574 20.381 ;
     RECT  16.38 19.661 16.398 20.525 ;
     RECT  17.568 19.757 18.198 20.525 ;
     RECT  19.152 20.237 19.71 20.525 ;
     RECT  21.672 19.997 33.678 20.525 ;
     RECT  21.708 20.525 24.822 20.573 ;
     RECT  25.596 20.525 33.318 20.573 ;
     RECT  26.1 20.573 32.922 20.669 ;
     RECT  21.708 20.573 21.762 21.389 ;
     RECT  17.568 20.525 17.586 21.485 ;
     RECT  21.744 21.389 21.762 21.485 ;
     RECT  23.076 20.573 23.742 21.485 ;
     RECT  24.804 20.573 24.822 21.485 ;
     RECT  26.1 20.669 32.886 21.485 ;
     RECT  26.1 21.485 32.31 21.563 ;
     RECT  26.118 21.563 26.172 21.569 ;
     RECT  26.19 21.563 26.244 21.569 ;
     RECT  26.262 21.563 26.316 21.569 ;
     RECT  26.334 21.563 26.388 21.569 ;
     RECT  26.406 21.563 26.46 21.569 ;
     RECT  26.478 21.563 26.532 21.569 ;
     RECT  26.55 21.563 26.604 21.569 ;
     RECT  26.622 21.563 26.676 21.569 ;
     RECT  26.694 21.563 26.748 21.569 ;
     RECT  26.766 21.563 26.82 21.569 ;
     RECT  26.838 21.563 26.892 21.569 ;
     RECT  26.91 21.563 26.964 21.569 ;
     RECT  26.982 21.563 27.036 21.569 ;
     RECT  27.054 21.563 27.108 21.569 ;
     RECT  27.126 21.563 27.18 21.569 ;
     RECT  27.198 21.563 27.252 21.569 ;
     RECT  27.27 21.563 27.324 21.569 ;
     RECT  27.342 21.563 27.396 21.569 ;
     RECT  27.414 21.563 27.468 21.569 ;
     RECT  27.486 21.563 27.54 21.569 ;
     RECT  27.558 21.563 27.612 21.569 ;
     RECT  27.63 21.563 27.684 21.569 ;
     RECT  27.702 21.563 27.756 21.569 ;
     RECT  27.774 21.563 27.828 21.569 ;
     RECT  27.846 21.563 27.9 21.569 ;
     RECT  27.918 21.563 27.972 21.569 ;
     RECT  27.99 21.563 28.044 21.569 ;
     RECT  28.062 21.563 28.116 21.569 ;
     RECT  28.134 21.563 28.188 21.569 ;
     RECT  28.206 21.563 28.26 21.569 ;
     RECT  28.278 21.563 28.332 21.569 ;
     RECT  28.35 21.563 28.404 21.569 ;
     RECT  28.422 21.563 28.476 21.569 ;
     RECT  28.494 21.563 28.548 21.569 ;
     RECT  28.566 21.563 28.62 21.569 ;
     RECT  28.638 21.563 28.692 21.569 ;
     RECT  28.71 21.563 28.764 21.569 ;
     RECT  28.782 21.563 28.836 21.569 ;
     RECT  28.854 21.563 28.908 21.569 ;
     RECT  28.926 21.563 28.98 21.569 ;
     RECT  28.998 21.563 29.052 21.569 ;
     RECT  29.07 21.563 29.124 21.569 ;
     RECT  29.142 21.563 29.196 21.569 ;
     RECT  29.214 21.563 29.268 21.569 ;
     RECT  29.286 21.563 29.34 21.569 ;
     RECT  29.358 21.563 29.412 21.569 ;
     RECT  29.43 21.563 29.484 21.569 ;
     RECT  29.502 21.563 29.556 21.569 ;
     RECT  29.574 21.563 29.628 21.569 ;
     RECT  29.646 21.563 29.7 21.569 ;
     RECT  29.718 21.563 29.772 21.569 ;
     RECT  29.79 21.563 29.844 21.569 ;
     RECT  29.862 21.563 29.916 21.569 ;
     RECT  29.934 21.563 29.988 21.569 ;
     RECT  30.006 21.563 30.06 21.569 ;
     RECT  30.078 21.563 30.132 21.569 ;
     RECT  30.15 21.563 30.204 21.569 ;
     RECT  30.222 21.563 30.276 21.569 ;
     RECT  30.294 21.563 30.348 21.569 ;
     RECT  30.366 21.563 30.42 21.569 ;
     RECT  30.438 21.563 30.492 21.569 ;
     RECT  30.51 21.563 30.564 21.569 ;
     RECT  30.582 21.563 30.636 21.569 ;
     RECT  30.654 21.563 30.708 21.569 ;
     RECT  30.726 21.563 30.78 21.569 ;
     RECT  30.798 21.563 30.852 21.569 ;
     RECT  30.87 21.563 30.924 21.569 ;
     RECT  30.942 21.563 30.996 21.569 ;
     RECT  31.014 21.563 31.068 21.569 ;
     RECT  31.086 21.563 31.14 21.569 ;
     RECT  31.158 21.563 31.212 21.569 ;
     RECT  31.23 21.563 31.284 21.569 ;
     RECT  31.302 21.563 31.356 21.569 ;
     RECT  31.374 21.563 31.428 21.569 ;
     RECT  31.446 21.563 31.5 21.569 ;
     RECT  31.518 21.563 31.572 21.569 ;
     RECT  31.59 21.563 31.644 21.569 ;
     RECT  31.662 21.563 31.716 21.569 ;
     RECT  31.734 21.563 31.788 21.569 ;
     RECT  31.806 21.563 31.86 21.569 ;
     RECT  31.878 21.563 31.932 21.569 ;
     RECT  31.95 21.563 32.004 21.569 ;
     RECT  32.022 21.563 32.076 21.569 ;
     RECT  32.094 21.563 32.31 21.569 ;
     RECT  26.118 21.569 26.172 21.581 ;
     RECT  26.19 21.569 26.244 21.581 ;
     RECT  26.262 21.569 26.316 21.581 ;
     RECT  26.334 21.569 26.388 21.581 ;
     RECT  26.406 21.569 26.46 21.581 ;
     RECT  26.478 21.569 26.532 21.581 ;
     RECT  26.55 21.569 26.604 21.581 ;
     RECT  26.622 21.569 26.676 21.581 ;
     RECT  26.694 21.569 26.748 21.581 ;
     RECT  26.766 21.569 26.82 21.581 ;
     RECT  26.838 21.569 26.892 21.581 ;
     RECT  26.91 21.569 26.964 21.581 ;
     RECT  26.982 21.569 27.036 21.581 ;
     RECT  27.054 21.569 27.108 21.581 ;
     RECT  27.126 21.569 27.18 21.581 ;
     RECT  27.198 21.569 27.252 21.581 ;
     RECT  27.27 21.569 27.324 21.581 ;
     RECT  27.342 21.569 27.396 21.581 ;
     RECT  27.414 21.569 27.468 21.581 ;
     RECT  27.486 21.569 27.54 21.581 ;
     RECT  27.558 21.569 27.612 21.581 ;
     RECT  27.63 21.569 27.684 21.581 ;
     RECT  27.702 21.569 27.756 21.581 ;
     RECT  27.774 21.569 27.828 21.581 ;
     RECT  27.846 21.569 27.9 21.581 ;
     RECT  27.918 21.569 27.972 21.581 ;
     RECT  27.99 21.569 28.044 21.581 ;
     RECT  28.062 21.569 28.116 21.581 ;
     RECT  28.134 21.569 28.188 21.581 ;
     RECT  28.206 21.569 28.26 21.581 ;
     RECT  28.278 21.569 28.332 21.581 ;
     RECT  28.35 21.569 28.404 21.581 ;
     RECT  28.422 21.569 28.476 21.581 ;
     RECT  28.494 21.569 28.548 21.581 ;
     RECT  28.566 21.569 28.62 21.581 ;
     RECT  28.638 21.569 28.692 21.581 ;
     RECT  28.71 21.569 28.764 21.581 ;
     RECT  28.782 21.569 28.836 21.581 ;
     RECT  28.854 21.569 28.908 21.581 ;
     RECT  28.926 21.569 28.98 21.581 ;
     RECT  28.998 21.569 29.052 21.581 ;
     RECT  29.07 21.569 29.124 21.581 ;
     RECT  29.142 21.569 29.196 21.581 ;
     RECT  29.214 21.569 29.268 21.581 ;
     RECT  29.286 21.569 29.34 21.581 ;
     RECT  29.358 21.569 29.412 21.581 ;
     RECT  29.43 21.569 29.484 21.581 ;
     RECT  29.502 21.569 29.556 21.581 ;
     RECT  29.574 21.569 29.628 21.581 ;
     RECT  29.646 21.569 29.7 21.581 ;
     RECT  29.718 21.569 29.772 21.581 ;
     RECT  29.79 21.569 29.844 21.581 ;
     RECT  29.862 21.569 29.916 21.581 ;
     RECT  29.934 21.569 29.988 21.581 ;
     RECT  30.006 21.569 30.06 21.581 ;
     RECT  30.078 21.569 30.132 21.581 ;
     RECT  30.15 21.569 30.204 21.581 ;
     RECT  30.222 21.569 30.276 21.581 ;
     RECT  30.294 21.569 30.348 21.581 ;
     RECT  30.366 21.569 30.42 21.581 ;
     RECT  30.438 21.569 30.492 21.581 ;
     RECT  30.51 21.569 30.564 21.581 ;
     RECT  30.582 21.569 30.636 21.581 ;
     RECT  30.654 21.569 30.708 21.581 ;
     RECT  30.726 21.569 30.78 21.581 ;
     RECT  30.798 21.569 30.852 21.581 ;
     RECT  30.87 21.569 30.924 21.581 ;
     RECT  30.942 21.569 30.996 21.581 ;
     RECT  31.014 21.569 31.068 21.581 ;
     RECT  31.086 21.569 31.14 21.581 ;
     RECT  31.158 21.569 31.212 21.581 ;
     RECT  31.23 21.569 31.284 21.581 ;
     RECT  31.302 21.569 31.356 21.581 ;
     RECT  31.374 21.569 31.428 21.581 ;
     RECT  31.446 21.569 31.5 21.581 ;
     RECT  31.518 21.569 31.572 21.581 ;
     RECT  31.59 21.569 31.644 21.581 ;
     RECT  31.662 21.569 31.716 21.581 ;
     RECT  31.734 21.569 31.788 21.581 ;
     RECT  31.806 21.569 31.86 21.581 ;
     RECT  31.878 21.569 31.932 21.581 ;
     RECT  31.95 21.569 32.004 21.581 ;
     RECT  32.022 21.569 32.076 21.581 ;
    LAYER M4 ;
     RECT  2.408 2.148 2.512 19.452 ;
     RECT  2.512 2.418 2.704 19.182 ;
     RECT  5.108 2.148 5.212 19.452 ;
     RECT  5.212 2.418 5.404 19.182 ;
     RECT  7.808 2.148 7.912 19.452 ;
     RECT  7.912 2.418 8.104 19.182 ;
     RECT  10.508 2.148 10.612 19.452 ;
     RECT  10.612 2.418 10.804 19.182 ;
     RECT  13.208 2.148 13.312 19.452 ;
     RECT  13.312 2.418 13.504 19.182 ;
     RECT  15.677 19.344 15.781 19.368 ;
     RECT  15.781 18.816 15.877 19.368 ;
     RECT  15.877 18.816 15.908 19.656 ;
     RECT  15.908 2.148 15.973 19.656 ;
     RECT  15.973 2.148 16.012 20.52 ;
     RECT  16.012 2.418 16.204 20.52 ;
     RECT  16.204 18.816 16.409 20.52 ;
     RECT  16.409 18.816 16.517 19.56 ;
     RECT  16.517 18.816 17.485 19.368 ;
     RECT  17.221 21.456 17.597 21.48 ;
     RECT  17.701 20.496 18.085 21.432 ;
     RECT  18.085 20.448 18.181 21.432 ;
     RECT  17.485 18.528 18.313 19.368 ;
     RECT  18.313 18.432 18.421 19.368 ;
     RECT  18.181 20.4 18.421 21.432 ;
     RECT  18.421 18.432 18.608 21.432 ;
     RECT  18.608 2.148 18.707 21.432 ;
     RECT  18.707 2.148 18.712 20.52 ;
     RECT  18.712 2.418 18.904 20.52 ;
     RECT  18.904 17.616 20.645 20.52 ;
     RECT  20.645 17.568 21.013 20.52 ;
     RECT  21.013 17.472 21.109 20.52 ;
     RECT  21.085 2.88 21.308 2.904 ;
     RECT  21.109 17.472 21.308 21.432 ;
     RECT  21.308 2.148 21.349 21.432 ;
     RECT  21.349 2.148 21.412 21.48 ;
     RECT  21.412 2.418 21.604 21.48 ;
     RECT  21.604 17.472 21.773 21.48 ;
     RECT  21.604 2.544 22.741 4.2 ;
     RECT  22.741 2.544 22.813 4.248 ;
     RECT  21.773 17.472 22.981 20.568 ;
     RECT  22.813 1.728 23.029 4.248 ;
     RECT  23.029 1.728 23.209 4.68 ;
     RECT  23.209 1.728 23.389 5.496 ;
     RECT  23.389 1.104 23.507 5.496 ;
     RECT  22.981 17.472 23.753 21.48 ;
     RECT  23.507 1.92 24.008 5.496 ;
     RECT  23.749 9.264 24.008 9.288 ;
     RECT  23.845 14.832 24.008 14.856 ;
     RECT  23.753 17.472 24.008 21.432 ;
     RECT  24.008 1.92 24.304 21.432 ;
     RECT  24.304 14.832 24.563 15.432 ;
     RECT  24.304 1.92 24.653 7.992 ;
     RECT  24.304 17.04 24.793 21.432 ;
     RECT  24.793 17.04 24.877 21.48 ;
     RECT  24.563 14.832 24.941 14.856 ;
     RECT  24.653 7.872 25.525 7.992 ;
     RECT  25.525 7.872 25.661 8.088 ;
     RECT  24.877 17.04 25.715 20.568 ;
     RECT  24.653 1.92 25.873 6.84 ;
     RECT  25.661 7.872 25.873 7.944 ;
     RECT  25.957 14.256 25.981 14.28 ;
     RECT  22.201 0.096 26.012 0.12 ;
     RECT  25.981 14.256 26.017 14.856 ;
     RECT  26.012 0.096 26.233 0.552 ;
     RECT  24.304 9.264 26.233 9.288 ;
     RECT  26.233 0.096 26.485 0.6 ;
     RECT  25.873 1.92 26.485 7.944 ;
     RECT  26.485 0.096 26.708 7.944 ;
     RECT  26.233 9.072 26.708 9.288 ;
     RECT  26.017 14.256 26.708 14.952 ;
     RECT  26.593 16.032 26.708 16.056 ;
     RECT  25.715 17.04 26.708 20.52 ;
     RECT  26.708 0.096 26.801 20.52 ;
     RECT  26.801 0.096 27.004 21.48 ;
     RECT  27.004 0.096 27.025 9.288 ;
     RECT  27.025 0.048 27.245 9.288 ;
     RECT  27.245 0.096 27.299 9.288 ;
     RECT  27.299 1.104 27.317 2.376 ;
     RECT  27.299 0.096 27.353 0.12 ;
     RECT  27.299 3.744 27.389 9.288 ;
     RECT  27.389 3.744 27.443 5.16 ;
     RECT  27.443 3.84 27.605 5.16 ;
     RECT  27.004 15.408 27.713 21.48 ;
     RECT  27.605 3.84 27.875 5.064 ;
     RECT  27.004 13.68 27.901 13.704 ;
     RECT  27.317 1.104 28.261 2.28 ;
     RECT  27.389 6.672 28.429 6.888 ;
     RECT  27.389 7.92 28.508 8.568 ;
     RECT  28.261 0.816 28.549 2.28 ;
     RECT  27.875 4.128 28.604 5.064 ;
     RECT  28.429 6.288 28.604 6.888 ;
     RECT  28.549 0.816 28.741 2.328 ;
     RECT  27.713 16.656 28.825 21.48 ;
     RECT  28.741 0.144 28.837 2.328 ;
     RECT  28.837 0.144 28.861 2.808 ;
     RECT  28.825 16.56 28.973 21.48 ;
     RECT  28.861 0.048 28.988 2.808 ;
     RECT  28.604 4.128 28.988 6.888 ;
     RECT  28.988 0.048 29.081 6.888 ;
     RECT  29.029 15.408 29.149 15.432 ;
     RECT  28.508 7.92 29.249 8.712 ;
     RECT  29.249 7.92 29.269 9.24 ;
     RECT  29.081 2.016 29.408 6.888 ;
     RECT  29.269 7.872 29.408 9.24 ;
     RECT  28.837 12.528 29.408 12.552 ;
     RECT  29.149 14.832 29.408 15.432 ;
     RECT  28.973 16.56 29.408 21.432 ;
     RECT  29.408 2.016 29.704 21.432 ;
     RECT  29.704 14.832 29.873 14.904 ;
     RECT  29.704 16.128 29.945 21.432 ;
     RECT  29.081 0.048 30.085 0.888 ;
     RECT  29.704 2.016 30.085 3.48 ;
     RECT  29.873 14.88 30.089 14.904 ;
     RECT  29.945 16.272 30.181 21.432 ;
     RECT  30.181 16.272 30.515 21.48 ;
     RECT  29.704 4.464 30.659 7.464 ;
     RECT  29.704 13.632 30.707 13.656 ;
     RECT  30.515 16.656 30.737 21.48 ;
     RECT  30.737 16.848 30.803 21.48 ;
     RECT  30.085 0.048 30.877 3.48 ;
     RECT  30.659 5.136 30.881 7.464 ;
     RECT  30.803 20.496 30.985 21.48 ;
     RECT  30.985 20.496 31.133 21.528 ;
     RECT  30.881 5.136 31.717 6.888 ;
     RECT  30.877 0.048 31.741 4.008 ;
     RECT  31.717 5.088 31.741 6.888 ;
     RECT  30.803 16.848 31.957 19.416 ;
     RECT  31.133 20.496 31.957 21.48 ;
     RECT  31.741 0.048 32.108 6.888 ;
     RECT  31.957 16.848 32.108 21.48 ;
     RECT  32.108 0.048 32.404 21.48 ;
     RECT  32.404 0.048 32.501 4.968 ;
     RECT  32.404 17.616 32.717 21.48 ;
     RECT  32.501 0.048 32.753 3.96 ;
     RECT  32.717 19.296 32.861 21.48 ;
     RECT  32.861 19.392 32.941 21.48 ;
     RECT  32.753 0.048 32.969 3.864 ;
     RECT  32.969 0.048 33.005 3.336 ;
     RECT  33.005 1.728 33.149 3.336 ;
     RECT  32.717 17.616 33.299 18.168 ;
     RECT  33.299 17.616 33.395 17.64 ;
     RECT  32.941 19.392 33.491 20.664 ;
     RECT  33.149 1.728 33.545 3 ;
     RECT  33.545 1.92 33.581 3 ;
     RECT  33.491 19.392 33.587 20.568 ;
     RECT  33.581 2.304 33.689 3 ;
     RECT  32.501 4.944 33.689 4.968 ;
     RECT  33.587 19.392 33.689 20.52 ;
     RECT  33.005 0.048 33.869 0.6 ;
     RECT  33.689 19.392 33.875 20.472 ;
     RECT  33.875 19.392 34.067 19.992 ;
     RECT  33.869 0.048 34.193 0.072 ;
     RECT  33.689 2.976 34.808 3 ;
     RECT  34.067 19.392 34.808 19.452 ;
     RECT  34.808 2.148 34.912 19.452 ;
     RECT  34.912 2.418 35.104 19.182 ;
     RECT  37.508 2.148 37.612 19.452 ;
     RECT  37.612 2.418 37.804 19.182 ;
     RECT  40.208 2.148 40.312 19.452 ;
     RECT  40.312 2.418 40.504 19.182 ;
     RECT  42.908 2.148 43.012 19.452 ;
     RECT  43.012 2.418 43.204 19.182 ;
     RECT  45.608 2.148 45.712 19.452 ;
     RECT  45.712 2.418 45.904 19.182 ;
     RECT  48.308 2.148 48.412 19.452 ;
     RECT  48.412 2.418 48.604 19.182 ;
     RECT  51.008 2.148 51.112 19.452 ;
     RECT  51.112 2.418 51.304 19.182 ;
    LAYER M5 ;
     RECT  26.088 0.016 26.16 0.084 ;
     RECT  26.184 0.016 26.256 0.084 ;
     RECT  26.28 0.016 26.352 0.084 ;
     RECT  26.376 0.016 26.448 0.084 ;
     RECT  26.472 0.016 26.544 0.084 ;
     RECT  26.568 0.016 26.64 0.084 ;
     RECT  26.664 0.016 26.736 0.084 ;
     RECT  26.76 0.016 26.832 0.084 ;
     RECT  26.856 0.016 26.928 0.084 ;
     RECT  26.952 0.016 27.024 0.084 ;
     RECT  27.048 0.016 27.12 0.084 ;
     RECT  27.144 0.016 27.216 0.084 ;
     RECT  27.24 0.016 27.312 0.084 ;
     RECT  27.336 0.016 27.408 0.084 ;
     RECT  27.432 0.016 27.504 0.084 ;
     RECT  27.528 0.016 27.6 0.084 ;
     RECT  27.624 0.016 27.696 0.084 ;
     RECT  27.72 0.016 27.792 0.084 ;
     RECT  27.816 0.016 27.888 0.084 ;
     RECT  27.912 0.016 27.984 0.084 ;
     RECT  28.008 0.016 28.08 0.084 ;
     RECT  28.104 0.016 28.176 0.084 ;
     RECT  28.2 0.016 28.272 0.084 ;
     RECT  28.296 0.016 28.368 0.084 ;
     RECT  28.392 0.016 28.464 0.084 ;
     RECT  28.488 0.016 28.56 0.084 ;
     RECT  28.584 0.016 28.656 0.084 ;
     RECT  28.68 0.016 28.752 0.084 ;
     RECT  28.776 0.016 28.848 0.084 ;
     RECT  28.872 0.016 28.944 0.084 ;
     RECT  28.968 0.016 29.04 0.084 ;
     RECT  29.064 0.016 29.136 0.084 ;
     RECT  29.16 0.016 29.232 0.084 ;
     RECT  29.256 0.016 29.328 0.084 ;
     RECT  29.352 0.016 29.424 0.084 ;
     RECT  29.448 0.016 29.52 0.084 ;
     RECT  29.544 0.016 29.616 0.084 ;
     RECT  29.64 0.016 29.712 0.084 ;
     RECT  29.736 0.016 29.808 0.084 ;
     RECT  29.832 0.016 29.904 0.084 ;
     RECT  29.928 0.016 30 0.084 ;
     RECT  30.024 0.016 30.096 0.084 ;
     RECT  30.12 0.016 30.192 0.084 ;
     RECT  30.216 0.016 30.288 0.084 ;
     RECT  30.312 0.016 30.384 0.084 ;
     RECT  30.408 0.016 30.48 0.084 ;
     RECT  30.504 0.016 30.576 0.084 ;
     RECT  30.6 0.016 30.672 0.084 ;
     RECT  30.696 0.016 30.768 0.084 ;
     RECT  30.792 0.016 30.864 0.084 ;
     RECT  30.888 0.016 30.96 0.084 ;
     RECT  30.984 0.016 31.056 0.084 ;
     RECT  31.08 0.016 31.152 0.084 ;
     RECT  31.176 0.016 31.248 0.084 ;
     RECT  31.272 0.016 31.344 0.084 ;
     RECT  31.368 0.016 31.44 0.084 ;
     RECT  31.464 0.016 31.536 0.084 ;
     RECT  31.56 0.016 31.632 0.084 ;
     RECT  31.656 0.016 31.728 0.084 ;
     RECT  31.752 0.016 31.824 0.084 ;
     RECT  31.848 0.016 31.92 0.084 ;
     RECT  31.944 0.016 32.016 0.084 ;
     RECT  32.04 0.016 32.112 0.084 ;
     RECT  26.064 0.084 32.136 0.563 ;
     RECT  23.016 0.016 23.088 0.084 ;
     RECT  23.112 0.016 23.184 0.084 ;
     RECT  23.208 0.016 23.28 0.084 ;
     RECT  23.304 0.016 23.376 0.084 ;
     RECT  23.4 0.016 23.472 0.084 ;
     RECT  23.496 0.016 23.568 0.084 ;
     RECT  23.592 0.016 23.664 0.084 ;
     RECT  23.688 0.016 23.76 0.084 ;
     RECT  23.784 0.016 23.856 0.084 ;
     RECT  22.992 0.084 23.88 1.763 ;
     RECT  23.184 1.763 23.88 2.137 ;
     RECT  26.16 0.563 32.136 2.137 ;
     RECT  2.4 2.137 2.52 2.151 ;
     RECT  5.1 2.137 5.22 2.151 ;
     RECT  7.8 2.137 7.92 2.151 ;
     RECT  10.5 2.137 10.62 2.151 ;
     RECT  13.2 2.137 13.32 2.151 ;
     RECT  15.9 2.137 16.02 2.151 ;
     RECT  18.6 2.137 18.72 2.151 ;
     RECT  21.3 2.137 21.42 2.151 ;
     RECT  23.184 2.137 24.12 2.151 ;
     RECT  26.16 2.137 32.22 2.151 ;
     RECT  34.8 2.137 34.92 2.151 ;
     RECT  37.5 2.137 37.62 2.151 ;
     RECT  40.2 2.137 40.32 2.151 ;
     RECT  42.9 2.137 43.02 2.151 ;
     RECT  45.6 2.137 45.72 2.151 ;
     RECT  48.3 2.137 48.42 2.151 ;
     RECT  51 2.137 51.12 2.151 ;
     RECT  23.184 2.151 24.312 2.291 ;
     RECT  21.3 2.151 21.612 2.773 ;
     RECT  23.568 2.291 24.312 2.773 ;
     RECT  26.16 2.151 32.412 2.773 ;
     RECT  26.112 2.773 32.412 2.821 ;
     RECT  23.568 2.773 24.888 3.301 ;
     RECT  25.968 2.821 32.412 3.301 ;
     RECT  23.568 3.301 32.412 3.443 ;
     RECT  21.3 2.773 22.2 3.635 ;
     RECT  23.568 3.443 24.888 4.165 ;
     RECT  23.328 4.165 24.888 4.739 ;
     RECT  25.968 3.443 32.412 5.171 ;
     RECT  23.328 4.739 24.504 5.507 ;
     RECT  31.728 5.171 32.412 5.987 ;
     RECT  23.76 5.507 24.504 7.765 ;
     RECT  25.968 5.171 30.696 7.957 ;
     RECT  25.536 7.957 30.696 8.099 ;
     RECT  25.968 8.099 30.696 8.723 ;
     RECT  23.76 7.765 24.552 9.299 ;
     RECT  28.848 8.723 30.696 12.563 ;
     RECT  29.04 12.563 30.696 13.667 ;
     RECT  25.968 8.723 27.864 13.715 ;
     RECT  25.968 13.715 27.624 14.291 ;
     RECT  23.856 9.299 24.552 14.867 ;
     RECT  26.016 14.291 27.624 14.867 ;
     RECT  24 14.867 24.552 15.443 ;
     RECT  26.112 14.867 27.624 15.443 ;
     RECT  29.04 13.667 29.712 15.443 ;
     RECT  29.4 15.443 29.712 16.117 ;
     RECT  29.4 16.117 29.88 16.261 ;
     RECT  29.4 16.261 30.504 16.789 ;
     RECT  24 15.443 24.312 17.029 ;
     RECT  26.112 15.443 27.528 17.029 ;
     RECT  29.28 16.789 30.504 17.077 ;
     RECT  32.1 5.987 32.412 17.077 ;
     RECT  28.704 17.077 30.504 17.125 ;
     RECT  24 17.029 27.528 17.171 ;
     RECT  28.704 17.125 30.552 17.173 ;
     RECT  31.536 17.077 32.412 17.173 ;
     RECT  21.3 3.635 21.612 17.557 ;
     RECT  18.6 2.151 18.912 17.605 ;
     RECT  20.688 17.557 21.612 17.605 ;
     RECT  28.704 17.173 32.412 17.605 ;
     RECT  24 17.171 24.312 17.797 ;
     RECT  23.904 17.797 24.312 17.941 ;
     RECT  23.568 17.941 24.312 18.037 ;
     RECT  22.944 18.037 24.312 18.181 ;
     RECT  25.296 17.171 27.528 18.181 ;
     RECT  22.944 18.181 27.528 18.229 ;
     RECT  28.704 17.605 33.384 18.229 ;
     RECT  15.9 2.151 16.212 18.805 ;
     RECT  18.6 17.605 21.612 18.805 ;
     RECT  15.792 18.805 17.064 19.141 ;
     RECT  18.288 18.805 21.864 19.141 ;
     RECT  15.792 19.141 21.864 19.189 ;
     RECT  22.944 18.229 33.384 19.189 ;
     RECT  15.792 19.189 33.384 19.333 ;
     RECT  15.696 19.333 33.384 19.381 ;
     RECT  34.8 2.151 35.112 19.381 ;
     RECT  2.4 2.151 2.712 19.449 ;
     RECT  5.1 2.151 5.412 19.449 ;
     RECT  7.8 2.151 8.112 19.449 ;
     RECT  10.5 2.151 10.812 19.449 ;
     RECT  13.2 2.151 13.512 19.449 ;
     RECT  15.696 19.381 35.112 19.449 ;
     RECT  37.5 2.151 37.812 19.449 ;
     RECT  40.2 2.151 40.512 19.449 ;
     RECT  42.9 2.151 43.212 19.449 ;
     RECT  45.6 2.151 45.912 19.449 ;
     RECT  48.3 2.151 48.612 19.449 ;
     RECT  51 2.151 51.312 19.449 ;
     RECT  2.4 19.449 2.52 19.463 ;
     RECT  5.1 19.449 5.22 19.463 ;
     RECT  7.8 19.449 7.92 19.463 ;
     RECT  10.5 19.449 10.62 19.463 ;
     RECT  13.2 19.449 13.32 19.463 ;
     RECT  15.696 19.449 34.92 19.463 ;
     RECT  37.5 19.449 37.62 19.463 ;
     RECT  40.2 19.449 40.32 19.463 ;
     RECT  42.9 19.449 43.02 19.463 ;
     RECT  45.6 19.449 45.72 19.463 ;
     RECT  48.3 19.449 48.42 19.463 ;
     RECT  51 19.449 51.12 19.463 ;
     RECT  15.696 19.463 34.056 21.516 ;
     RECT  15.72 21.516 15.792 21.584 ;
     RECT  15.816 21.516 15.888 21.584 ;
     RECT  15.912 21.516 15.984 21.584 ;
     RECT  16.008 21.516 16.08 21.584 ;
     RECT  16.104 21.516 16.176 21.584 ;
     RECT  16.2 21.516 16.272 21.584 ;
     RECT  16.296 21.516 16.368 21.584 ;
     RECT  16.392 21.516 16.464 21.584 ;
     RECT  16.488 21.516 16.56 21.584 ;
     RECT  16.584 21.516 16.656 21.584 ;
     RECT  16.68 21.516 16.752 21.584 ;
     RECT  16.776 21.516 16.848 21.584 ;
     RECT  16.872 21.516 16.944 21.584 ;
     RECT  16.968 21.516 17.04 21.584 ;
     RECT  17.064 21.516 17.136 21.584 ;
     RECT  17.16 21.516 17.232 21.584 ;
     RECT  17.256 21.516 17.328 21.584 ;
     RECT  17.352 21.516 17.424 21.584 ;
     RECT  17.448 21.516 17.52 21.584 ;
     RECT  17.544 21.516 17.616 21.584 ;
     RECT  17.64 21.516 17.712 21.584 ;
     RECT  17.736 21.516 17.808 21.584 ;
     RECT  17.832 21.516 17.904 21.584 ;
     RECT  17.928 21.516 18 21.584 ;
     RECT  18.024 21.516 18.096 21.584 ;
     RECT  18.12 21.516 18.192 21.584 ;
     RECT  18.216 21.516 18.288 21.584 ;
     RECT  18.312 21.516 18.384 21.584 ;
     RECT  18.408 21.516 18.48 21.584 ;
     RECT  18.504 21.516 18.576 21.584 ;
     RECT  18.6 21.516 18.672 21.584 ;
     RECT  18.696 21.516 18.768 21.584 ;
     RECT  18.792 21.516 18.864 21.584 ;
     RECT  18.888 21.516 18.96 21.584 ;
     RECT  18.984 21.516 19.056 21.584 ;
     RECT  19.08 21.516 19.152 21.584 ;
     RECT  19.176 21.516 19.248 21.584 ;
     RECT  19.272 21.516 19.344 21.584 ;
     RECT  19.368 21.516 19.44 21.584 ;
     RECT  19.464 21.516 19.536 21.584 ;
     RECT  19.56 21.516 19.632 21.584 ;
     RECT  19.656 21.516 19.728 21.584 ;
     RECT  19.752 21.516 19.824 21.584 ;
     RECT  19.848 21.516 19.92 21.584 ;
     RECT  19.944 21.516 20.016 21.584 ;
     RECT  20.04 21.516 20.112 21.584 ;
     RECT  20.136 21.516 20.208 21.584 ;
     RECT  20.232 21.516 20.304 21.584 ;
     RECT  20.328 21.516 20.4 21.584 ;
     RECT  20.424 21.516 20.496 21.584 ;
     RECT  20.52 21.516 20.592 21.584 ;
     RECT  20.616 21.516 20.688 21.584 ;
     RECT  20.712 21.516 20.784 21.584 ;
     RECT  20.808 21.516 20.88 21.584 ;
     RECT  20.904 21.516 20.976 21.584 ;
     RECT  21 21.516 21.072 21.584 ;
     RECT  21.096 21.516 21.168 21.584 ;
     RECT  21.192 21.516 21.264 21.584 ;
     RECT  21.288 21.516 21.36 21.584 ;
     RECT  21.384 21.516 21.456 21.584 ;
     RECT  21.48 21.516 21.552 21.584 ;
     RECT  21.576 21.516 21.648 21.584 ;
     RECT  21.672 21.516 21.744 21.584 ;
     RECT  21.768 21.516 21.84 21.584 ;
     RECT  21.864 21.516 21.936 21.584 ;
     RECT  21.96 21.516 22.032 21.584 ;
     RECT  22.056 21.516 22.128 21.584 ;
     RECT  22.152 21.516 22.224 21.584 ;
     RECT  22.248 21.516 22.32 21.584 ;
     RECT  22.344 21.516 22.416 21.584 ;
     RECT  22.44 21.516 22.512 21.584 ;
     RECT  22.536 21.516 22.608 21.584 ;
     RECT  22.632 21.516 22.704 21.584 ;
     RECT  22.728 21.516 22.8 21.584 ;
     RECT  22.824 21.516 22.896 21.584 ;
     RECT  22.92 21.516 22.992 21.584 ;
     RECT  23.016 21.516 23.088 21.584 ;
     RECT  23.112 21.516 23.184 21.584 ;
     RECT  23.208 21.516 23.28 21.584 ;
     RECT  23.304 21.516 23.376 21.584 ;
     RECT  23.4 21.516 23.472 21.584 ;
     RECT  23.496 21.516 23.568 21.584 ;
     RECT  23.592 21.516 23.664 21.584 ;
     RECT  23.688 21.516 23.76 21.584 ;
     RECT  23.784 21.516 23.856 21.584 ;
     RECT  23.88 21.516 23.952 21.584 ;
     RECT  23.976 21.516 24.048 21.584 ;
     RECT  24.072 21.516 24.144 21.584 ;
     RECT  24.168 21.516 24.24 21.584 ;
     RECT  24.264 21.516 24.336 21.584 ;
     RECT  24.36 21.516 24.432 21.584 ;
     RECT  24.456 21.516 24.528 21.584 ;
     RECT  24.552 21.516 24.624 21.584 ;
     RECT  24.648 21.516 24.72 21.584 ;
     RECT  24.744 21.516 24.816 21.584 ;
     RECT  24.84 21.516 24.912 21.584 ;
     RECT  24.936 21.516 25.008 21.584 ;
     RECT  25.032 21.516 25.104 21.584 ;
     RECT  25.128 21.516 25.2 21.584 ;
     RECT  25.224 21.516 25.296 21.584 ;
     RECT  25.32 21.516 25.392 21.584 ;
     RECT  25.416 21.516 25.488 21.584 ;
     RECT  25.512 21.516 25.584 21.584 ;
     RECT  25.608 21.516 25.68 21.584 ;
     RECT  25.704 21.516 25.776 21.584 ;
     RECT  25.8 21.516 25.872 21.584 ;
     RECT  25.896 21.516 25.968 21.584 ;
     RECT  25.992 21.516 26.064 21.584 ;
     RECT  26.088 21.516 26.16 21.584 ;
     RECT  26.184 21.516 26.256 21.584 ;
     RECT  26.28 21.516 26.352 21.584 ;
     RECT  26.376 21.516 26.448 21.584 ;
     RECT  26.472 21.516 26.544 21.584 ;
     RECT  26.568 21.516 26.64 21.584 ;
     RECT  26.664 21.516 26.736 21.584 ;
     RECT  26.76 21.516 26.832 21.584 ;
     RECT  26.856 21.516 26.928 21.584 ;
     RECT  26.952 21.516 27.024 21.584 ;
     RECT  27.048 21.516 27.12 21.584 ;
     RECT  27.144 21.516 27.216 21.584 ;
     RECT  27.24 21.516 27.312 21.584 ;
     RECT  27.336 21.516 27.408 21.584 ;
     RECT  27.432 21.516 27.504 21.584 ;
     RECT  27.528 21.516 27.6 21.584 ;
     RECT  27.624 21.516 27.696 21.584 ;
     RECT  27.72 21.516 27.792 21.584 ;
     RECT  27.816 21.516 27.888 21.584 ;
     RECT  27.912 21.516 27.984 21.584 ;
     RECT  28.008 21.516 28.08 21.584 ;
     RECT  28.104 21.516 28.176 21.584 ;
     RECT  28.2 21.516 28.272 21.584 ;
     RECT  28.296 21.516 28.368 21.584 ;
     RECT  28.392 21.516 28.464 21.584 ;
     RECT  28.488 21.516 28.56 21.584 ;
     RECT  28.584 21.516 28.656 21.584 ;
     RECT  28.68 21.516 28.752 21.584 ;
     RECT  28.776 21.516 28.848 21.584 ;
     RECT  28.872 21.516 28.944 21.584 ;
     RECT  28.968 21.516 29.04 21.584 ;
     RECT  29.064 21.516 29.136 21.584 ;
     RECT  29.16 21.516 29.232 21.584 ;
     RECT  29.256 21.516 29.328 21.584 ;
     RECT  29.352 21.516 29.424 21.584 ;
     RECT  29.448 21.516 29.52 21.584 ;
     RECT  29.544 21.516 29.616 21.584 ;
     RECT  29.64 21.516 29.712 21.584 ;
     RECT  29.736 21.516 29.808 21.584 ;
     RECT  29.832 21.516 29.904 21.584 ;
     RECT  29.928 21.516 30 21.584 ;
     RECT  30.024 21.516 30.096 21.584 ;
     RECT  30.12 21.516 30.192 21.584 ;
     RECT  30.216 21.516 30.288 21.584 ;
     RECT  30.312 21.516 30.384 21.584 ;
     RECT  30.408 21.516 30.48 21.584 ;
     RECT  30.504 21.516 30.576 21.584 ;
     RECT  30.6 21.516 30.672 21.584 ;
     RECT  30.696 21.516 30.768 21.584 ;
     RECT  30.792 21.516 30.864 21.584 ;
     RECT  30.888 21.516 30.96 21.584 ;
     RECT  30.984 21.516 31.056 21.584 ;
     RECT  31.08 21.516 31.152 21.584 ;
     RECT  31.176 21.516 31.248 21.584 ;
     RECT  31.272 21.516 31.344 21.584 ;
     RECT  31.368 21.516 31.44 21.584 ;
     RECT  31.464 21.516 31.536 21.584 ;
     RECT  31.56 21.516 31.632 21.584 ;
     RECT  31.656 21.516 31.728 21.584 ;
     RECT  31.752 21.516 31.824 21.584 ;
     RECT  31.848 21.516 31.92 21.584 ;
     RECT  31.944 21.516 32.016 21.584 ;
     RECT  32.04 21.516 32.112 21.584 ;
     RECT  32.136 21.516 32.208 21.584 ;
     RECT  32.232 21.516 32.304 21.584 ;
     RECT  32.328 21.516 32.4 21.584 ;
     RECT  32.424 21.516 32.496 21.584 ;
     RECT  32.52 21.516 32.592 21.584 ;
     RECT  32.616 21.516 32.688 21.584 ;
     RECT  32.712 21.516 32.784 21.584 ;
     RECT  32.808 21.516 32.88 21.584 ;
     RECT  32.904 21.516 32.976 21.584 ;
     RECT  33 21.516 33.072 21.584 ;
     RECT  33.096 21.516 33.168 21.584 ;
     RECT  33.192 21.516 33.264 21.584 ;
     RECT  33.288 21.516 33.36 21.584 ;
     RECT  33.384 21.516 33.456 21.584 ;
     RECT  33.48 21.516 33.552 21.584 ;
     RECT  33.576 21.516 33.648 21.584 ;
     RECT  33.672 21.516 33.744 21.584 ;
     RECT  33.768 21.516 33.84 21.584 ;
     RECT  33.864 21.516 33.936 21.584 ;
     RECT  33.96 21.516 34.032 21.584 ;
     RECT  22.992 1.763 23.184 2.151 ;
     RECT  21.612 2.151 23.184 2.291 ;
     RECT  21.612 2.291 23.568 2.773 ;
     RECT  22.2 2.773 23.568 3.635 ;
     RECT  24.888 2.773 26.112 2.821 ;
     RECT  24.888 2.821 25.968 3.301 ;
     RECT  24.888 3.443 25.968 4.739 ;
     RECT  23.328 3.635 23.568 4.165 ;
     RECT  24.504 4.739 25.968 7.765 ;
     RECT  30.696 5.171 31.728 5.987 ;
     RECT  30.696 5.987 32.1 13.667 ;
     RECT  24.552 7.765 25.968 7.957 ;
     RECT  24.552 7.957 25.536 8.099 ;
     RECT  24.552 8.099 25.968 14.291 ;
     RECT  27.864 8.723 28.848 12.563 ;
     RECT  27.864 12.563 29.04 13.715 ;
     RECT  27.624 13.715 29.04 15.443 ;
     RECT  24.552 14.291 26.016 14.867 ;
     RECT  29.28 15.443 29.4 16.789 ;
     RECT  27.528 17.077 28.704 18.229 ;
     RECT  30.504 17.077 31.536 17.125 ;
     RECT  30.552 17.125 31.536 17.173 ;
     RECT  24.312 17.171 25.296 18.181 ;
     RECT  33.384 17.605 34.8 19.381 ;
     RECT  21.612 18.037 22.944 18.805 ;
     RECT  17.064 18.805 18.288 19.141 ;
     RECT  21.864 18.805 22.944 19.189 ;
  END
END hbfd_lh_136_SN_f2
END LIBRARY
